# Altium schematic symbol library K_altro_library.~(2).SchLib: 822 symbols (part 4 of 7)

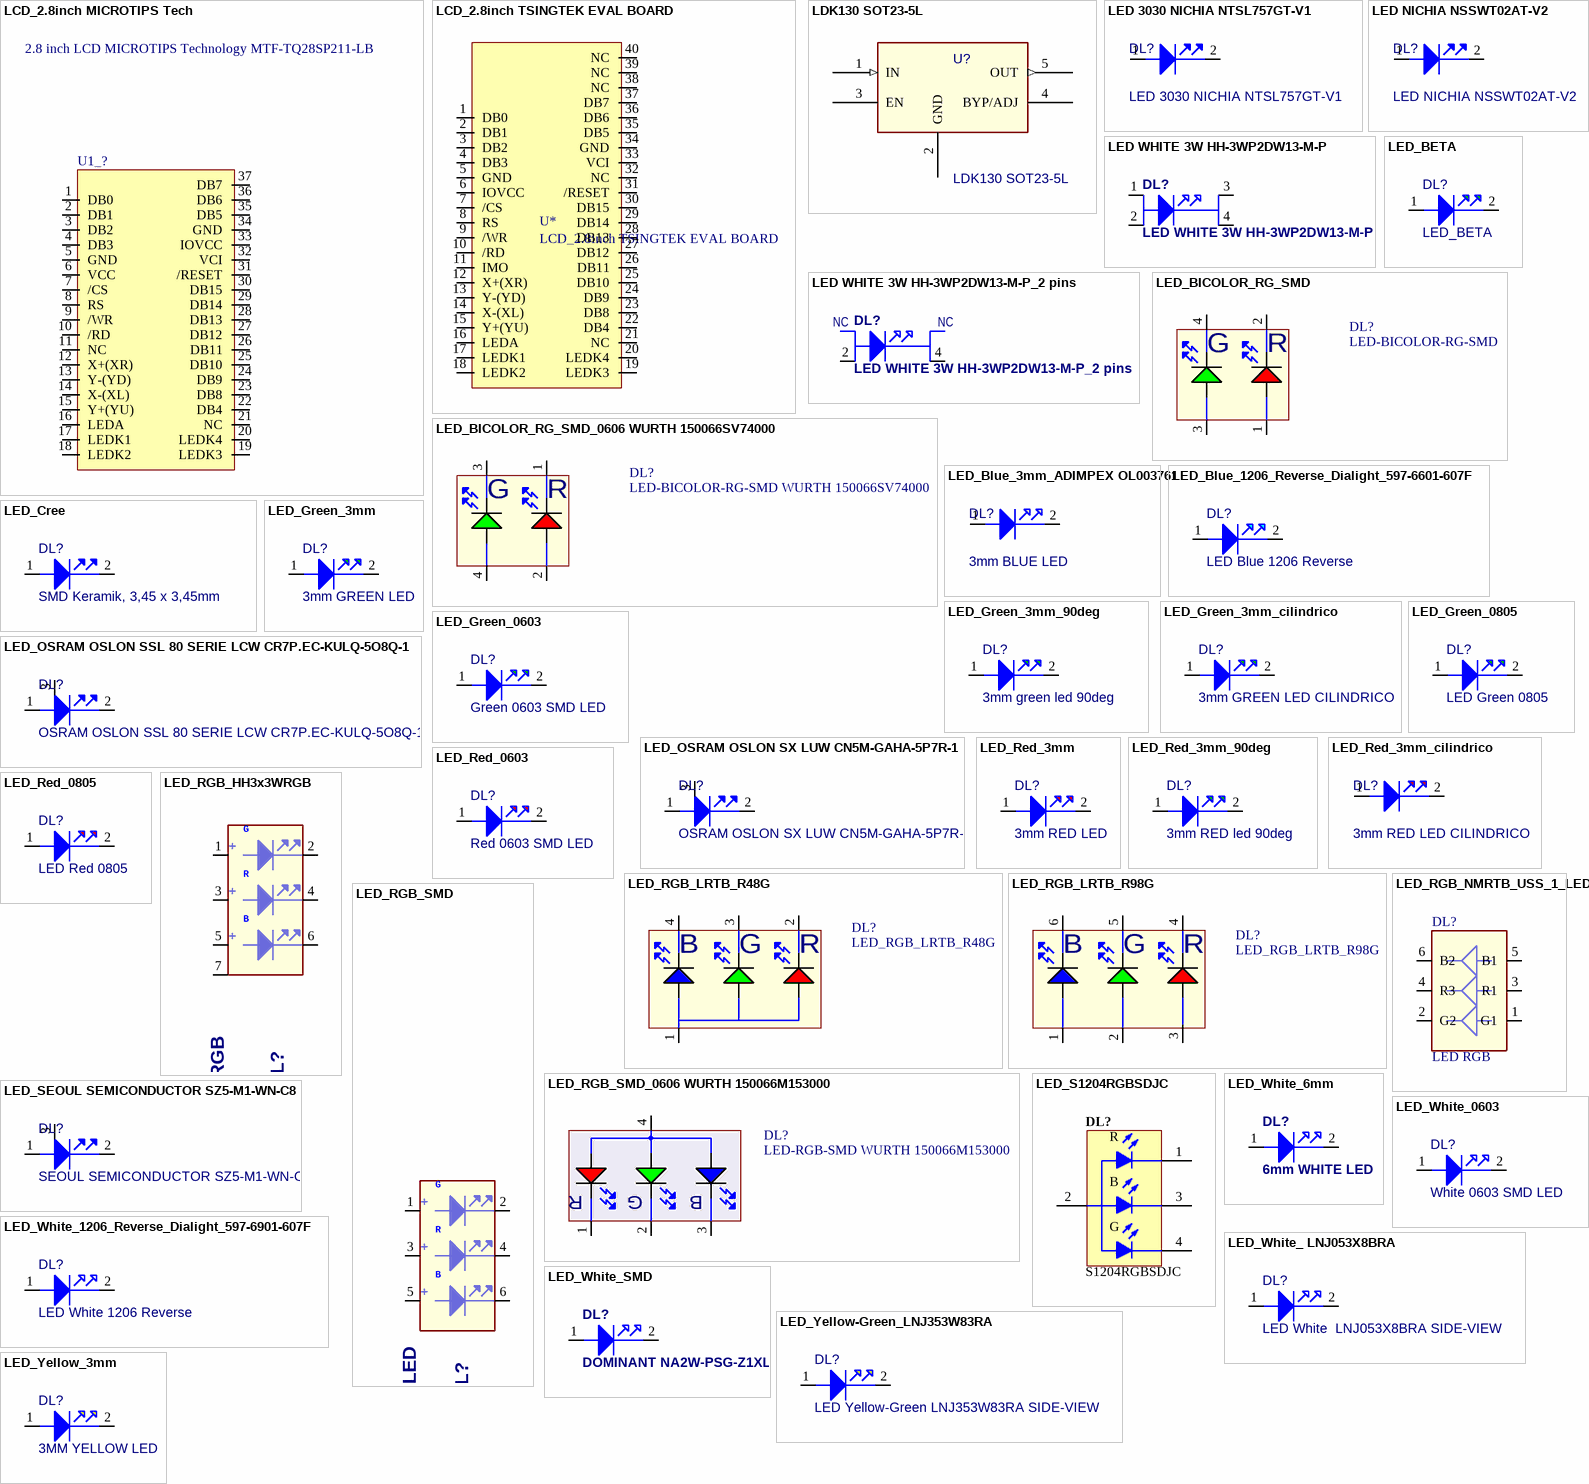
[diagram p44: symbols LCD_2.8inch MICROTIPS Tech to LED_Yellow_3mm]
## LED_Red_3mm_90deg
designator DL?, comment 3mm RED led 90deg
LED Red 3mm 90deg; Costo: 0,3; Aggiornato: s; ContoLavoro: 0
footprint 3MM RED LED 90deg H5 (Footprint not found)
pins: 1 ANODE, 2 CATHODE

## LED_Red_3mm_cilindrico
designator DL?, comment 3mm RED LED CILINDRICO
LED Red 3mm CILINDRICO; Costo: 0,10; SizeCode: Dia. 3mm; Aggiornato: s; ContoLavoro: 0
footprint 3MM CILINDRIC RED LED-DIST14mm
footprint 3MM CILINDRIC RED LED-DIST20mm
footprint 3MM CILINDRIC RED LED
pins: 1 ANODE, 2 CATHODE

## LED_Red_0603
designator DL?, comment Red 0603 SMD LED
LED Red 0603; Costo: 0; SizeCode: 0603; Aggiornato: NO
footprint 0603N_LED
pins: 1 ANODE, 2 CATHODE

## LED_Red_0805
designator DL?, comment LED Red 0805
Costo: 0,09; SizeCode: 0805; Aggiornato: S; ContoLavoro: 0
footprint LED_0805
pins: 1 ANODE, 2 CATHODE

## LED_RGB_HH3x3WRGB
designator DL?, comment RGB SMD LED HH3x3WRGB
LED RGB; Hpcode: LED0RGB001; Costo: 0,9; Aggiornato: NO; ContoLavoro: 0
footprint RGB_NMRTB_USS_1_LED
footprint RGB_NMRTB_USS_1_LED_new
footprint LED_HH3x3WRGB
pins: 1 ANODE1, 2 CATHODE1, 3 ANODE2, 4 CATHODE2, 5 ANODE3, 6 CATHODE3, 7 DIS

## LED_RGB_LRTB_R48G
designator DL?
LED RGB LRTB_R48G; Detail: € RS Pz>25; Costo: 0,148; Aggiornato: NO; ContoLavoro: 0
footprint LED_LRTB_R48G (Footprint not found)
pins: 1 AN, 2 R_CAT, 3 G_CAT, 4 B_CAT

## LED_RGB_LRTB_R98G
designator DL?
LED RGB LRTB_R98G; Detail: € RS Pz>50; Costo: 0,259; Aggiornato: NO; ContoLavoro: 0
footprint LED_LRTB_R98G
pins: 1 B_AN, 2 G_AN, 3 R_AN, 4 R_CAT, 5 G_CAT, 6 B_CAT

## LED_RGB_NMRTB_USS_1_LED
designator DL?, comment LED RGB
Costo: 0; Aggiornato: NO
footprint RGB_NMRTB_USS_1_LED
pins: 1 G1, 2 G2, 3 R1, 4 R3, 5 B1, 6 B2

## LED_RGB_SMD
designator DL?, comment DOMINANT NMRTB-WSG-AAB+ABD+X2Y-1 RGB LED
LED RGB SMD; Costo: 0; Aggiornato: NO
footprint RGB_NMRTB_USS_1_LED
footprint RGB_NMRTB_USS_1_LED_new
pins: 1 ANODE1, 2 CATHODE1, 3 ANODE2, 4 CATHODE2, 5 ANODE3, 6 CATHODE3

## LED_RGB_SMD_0606 WURTH 150066M153000
designator DL?, comment LED-RGB-SMD WURTH 150066M153000
Detail: 0,075€ 4000pcs offerta A20IT011754; Costo: 0,075; Aggiornato: S; ContoLavoro: 0
footprint LED_RGB_0606_WE_150066M153000 (LED RGB 1.6x1.6)
pins: 1 AN, 2 R_CAT, 3 G_CAT, 4 B_CAT

## LED_S1204RGBSDJC
designator DL?, comment S1204RGBSDJC
SASEN LED, RGB, SMD; Aggiornato: NO; Costo: 0
footprint S1204RGBSDJC
pins: 1 R, 2 A2, 3 B, 4 G

## LED_SEOUL SEMICONDUCTOR SZ5-M1-WN-C8
designator DL?, comment SEOUL SEMICONDUCTOR SZ5-M1-WN-C8
Detail: MATELICI ELNA; Aggiornato: si; ContoLavoro: 1
footprint LED_SEOUL SEMICONDUCTOR SZ5-M1-WN-C8 (Footprint not found)
pins: 1 ANODE, 2 CATHODE, 3 HEATER

## LED_White_6mm
designator DL?, comment 6mm WHITE LED
LED White 6mm; Hpcode: DIL6MMWHT; SizeCode: Dia. 6mm; Costo: 0; Aggiornato: NO
footprint 6MM LED (Footprint not found)
footprint 6mm_LED
pins: 1 ANODE, 2 CATHODE

## LED_White_0603
designator DL?, comment White 0603 SMD LED
LED White 0603; Detail: prezzo RS >50pz; Costo: 0,134; SizeCode: 0603; Aggiornato: n; ContoLavoro: 0
footprint 0603N_LED
pins: 1 ANODE, 2 CATHODE

## LED_White_1206_Reverse_Dialight_597-6901-607F
designator DL?, comment LED White 1206 Reverse
LED 597-6901-607F; Detail: € RS Pz>250; Costo: 0,25; SizeCode: 1206; Aggiornato: n; ContoLavoro: 0
footprint 1206_REVERSE_LED_Dialight_White (Footprint not found)
pins: 1 ANODE, 2 CATHODE

## LED_White_ LNJ053X8BRA
designator DL?, comment LED White  LNJ053X8BRA SIDE-VIEW
Detail: € Rs Pz>50; Costo: 0,274; SizeCode: KLTFSN2K5300; Aggiornato: s; ContoLavoro: 0
footprint LED_KLTFSN2K5300
simulation model DLED_GEN
pins: 1 ANODE, 2 CATHODE

## LED_White_SMD
designator DL?, comment DOMINANT NA2W-PSG-Z1XL
LED White SMD; Hpcode: LED0WHT001; Costo: 0; Aggiornato: NO
footprint 6MM LED (Footprint not found)
footprint DOMINANT_NA2WPSG
pins: 1 ANODE, 2 CATHODE

## LED_Yellow-Green_LNJ353W83RA
designator DL?, comment LED Yellow-Green LNJ353W83RA SIDE-VIEW
Detail: € Rs Pz>50; Costo: 0,235; SizeCode: KLTFSN2K5300; Aggiornato: s; ContoLavoro: 0
footprint LED_KLTFSN2K5300
simulation model DLED_GEN
pins: 1 ANODE, 2 CATHODE

## LED_Yellow_3mm
designator DL?, comment 3MM YELLOW LED
LED Yellow 3mm; Hpcode: DIL3MMYEL; SizeCode: Dia. 3mm; Costo: 0,10; Aggiornato: s; ContoLavoro: 0
footprint 3MM LED
simulation model DLED_GEN
footprint 3mm LED-DIST16mm (Footprint not found)
footprint 3mm LED-DIST22mm (Footprint not found)
pins: 1 ANODE, 2 CATHODE


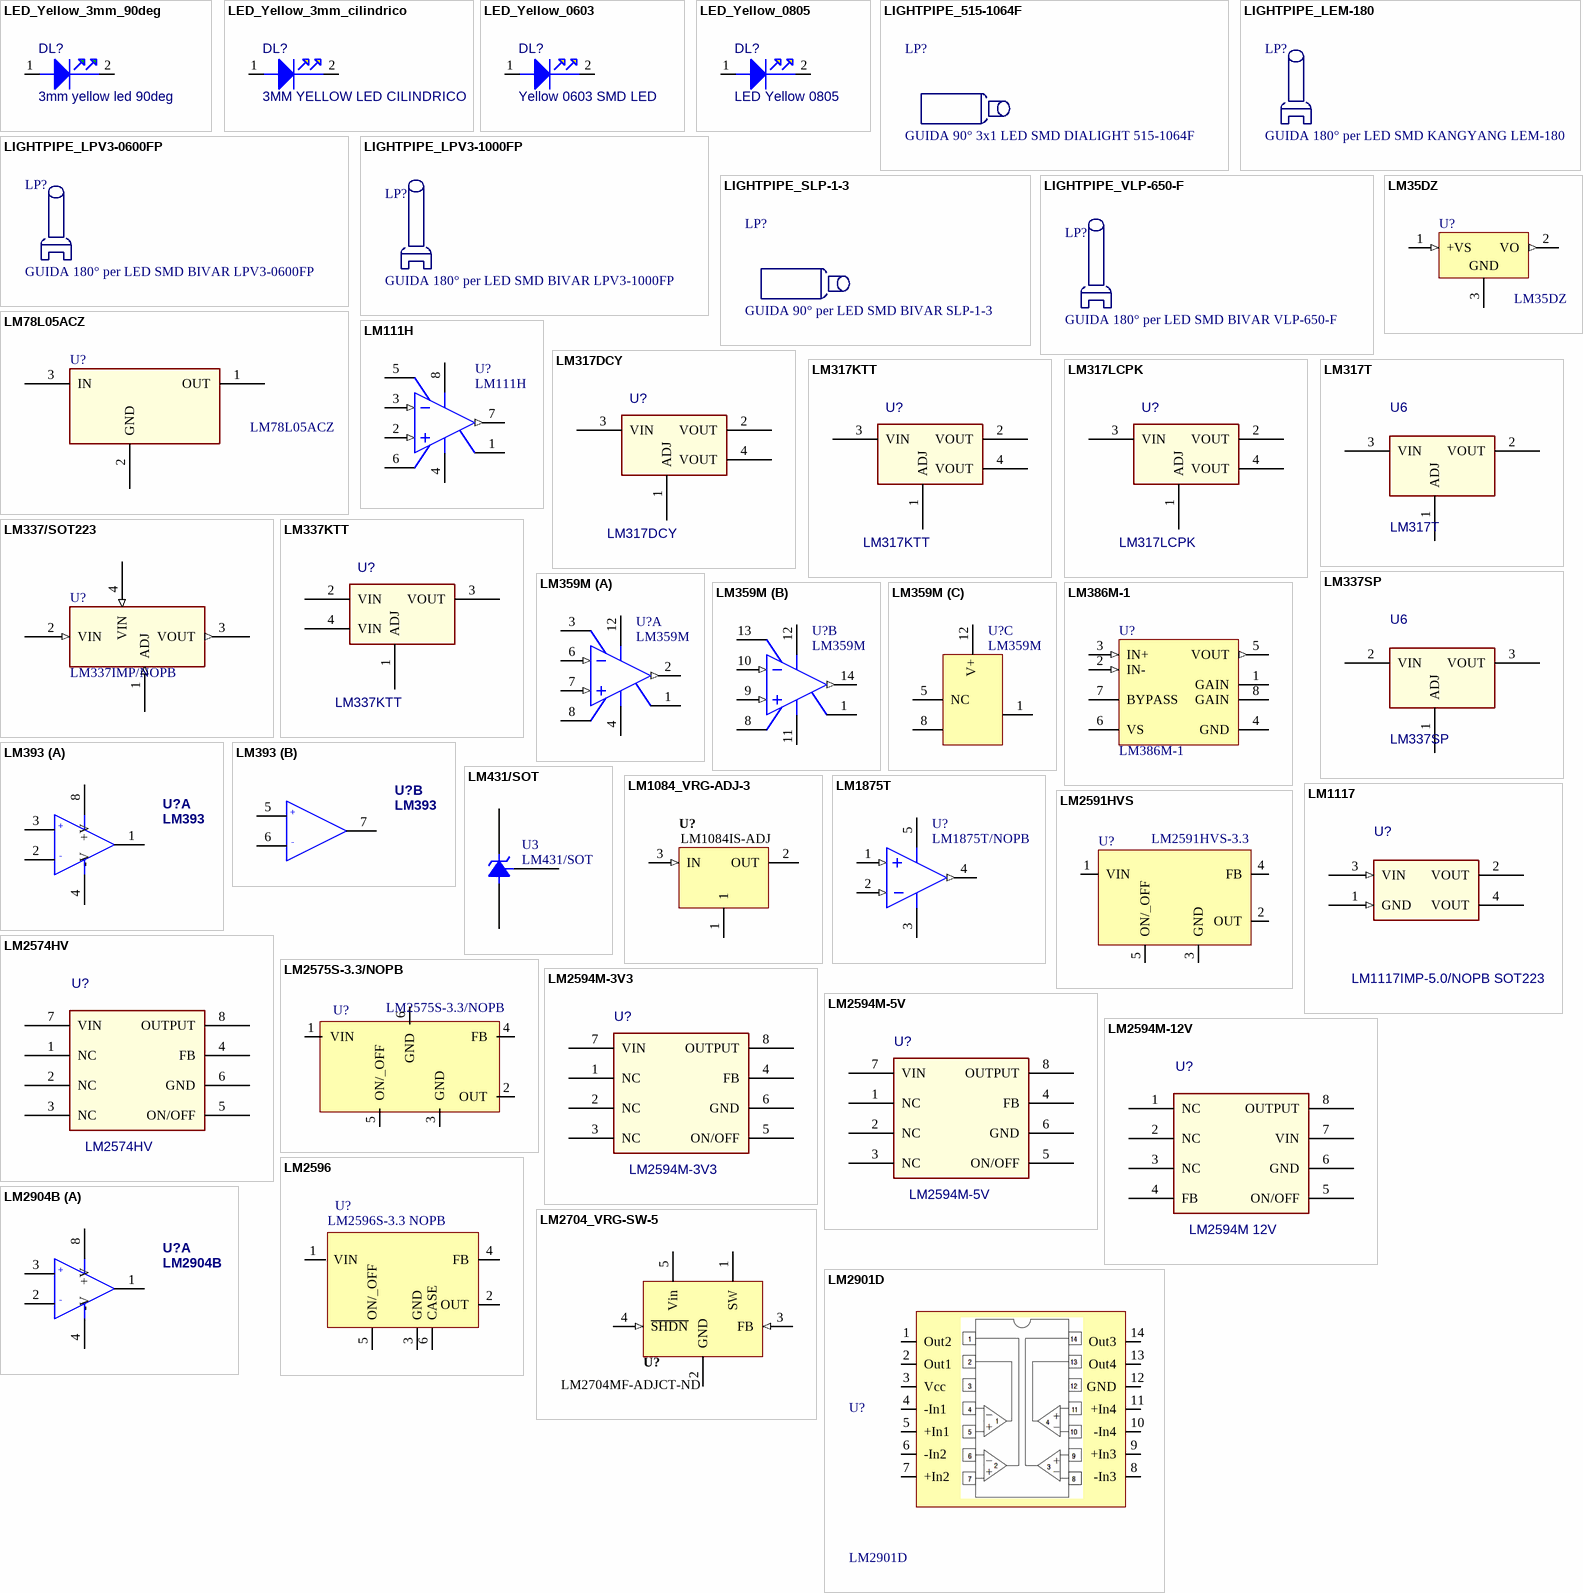
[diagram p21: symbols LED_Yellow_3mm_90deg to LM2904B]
## LED_Yellow_3mm_90deg
designator DL?, comment 3mm yellow led 90deg
LED Yellow 3mm 90deg; Costo: 1,8; Aggiornato: s; ContoLavoro: 0
footprint 3MM YEL LED 90deg H5 (Footprint not found)
simulation model DLED_GEN
pins: 1 ANODE, 2 CATHODE

## LED_Yellow_3mm_cilindrico
designator DL?, comment 3MM YELLOW LED CILINDRICO
LED Yellow 3mm CILINDRICO; SizeCode: Dia. 3mm; Costo: 0,10; Aggiornato: s; ContoLavoro: 0
footprint 3MM CILINDRIC YEL LED-DIST14mm
footprint 3MM CILINDRIC YEL LED-DIST20mm
footprint 3MM CILINDRIC YEL LED
simulation model DLED_GEN
pins: 1 ANODE, 2 CATHODE

## LED_Yellow_0603
designator DL?, comment Yellow 0603 SMD LED
LED Yellow 0603; Costo: 0; SizeCode: 0603; Aggiornato: NO
footprint 0603N_LED
pins: 1 ANODE, 2 CATHODE

## LED_Yellow_0805
designator DL?, comment LED Yellow 0805
Costo: 0,09; SizeCode: 0805; Aggiornato: s; ContoLavoro: 0
footprint LED_0805
simulation model DLED_GEN
pins: 1 ANODE, 2 CATHODE

## LIGHTPIPE_515-1064F
designator LP?, comment GUIDA 90° 3x1 LED SMD DIALIGHT 515-1064F  (no BOM)
Costo: 1; Hpcode: MMBLC153; Aggiornato: S; Detail: Parte meccanica non parte della scheda
footprint Lightpipe 3x1 (Dialight 515-1064F)
1 alternate drawing of the same symbol

## LIGHTPIPE_LEM-180
designator LP?, comment GUIDA 180° per LED SMD KANGYANG LEM-180
Costo: 0,075; Hpcode: MMBLC100; Aggiornato: S; Detail: Quotazione Orlandi HTcompo LEM-180 € 75,00/1000pcs Lead time: 2WK; ContoLavoro: 1
footprint GUIDA KANGYANG 180° LEM-180 per LED SMD (Footprint not found)
footprint GUIDA KANGYANG 180° LEM per LED SMD-IBRID_LPV_e_VLP_MONTATO_LEM-180 (Footprint not found)
1 alternate drawing of the same symbol

## LIGHTPIPE_LPV3-0600FP
designator LP?, comment GUIDA 180° per LED SMD BIVAR LPV3-0600FP
Costo: 0; Aggiornato: S; ContoLavoro: 1
footprint GUIDA BIVAR 180° LPV3-0600FP per LED SMD (Footprint not found)
footprint GUIDA BIVAR 180° VLP per LED SMD-IBRID_LPV_MONTATO_LPV3-0600FP
1 alternate drawing of the same symbol

## LIGHTPIPE_LPV3-1000FP
designator LP?, comment GUIDA 180° per LED SMD BIVAR LPV3-1000FP
Costo: 0; Aggiornato: S; ContoLavoro: 1
footprint GUIDA BIVAR 180° LPV3-1000FP per LED SMD
footprint GUIDA BIVAR 180° VLP per LED SMD-IBRID_LPV_MONTATO_LPV3-1000FP
1 alternate drawing of the same symbol

## LIGHTPIPE_SLP-1-3
designator LP?, comment GUIDA 90° per LED SMD BIVAR SLP-1-3  (no BOM)
Costo: 0,5; Hpcode: MMBLC094; Aggiornato: S; Detail: Parte meccanica non parte della scheda; ContoLavoro: 1
footprint GUIDA_BIVAR_90°_SLP-1-3 (Guida 90° per led SMD)
1 alternate drawing of the same symbol

## LIGHTPIPE_VLP-650-F
designator LP?, comment GUIDA 180° per LED SMD BIVAR VLP-650-F
Costo: 0,308; Aggiornato: S; Detail: 0,308€ Mouser Pz> 25; ContoLavoro: 1
footprint GUIDA BIVAR 180° VLP-650-F per LED SMD (Footprint not found)
footprint GUIDA BIVAR 180° VLP per LED SMD-IBRID_LPV_MONTATO_VLP-650-F
1 alternate drawing of the same symbol

## LM35DZ
designator U?
Precision Centigrade Temperature Sensor; Costo: 0; DeviceFunction: Temperature Sensors; Aggiornato: NO
footprint Z03A (TO, Flat Index; 3 In-Line, Axial Leads; Body Dia. 5mm; Leads 0.55 x 0.50 mm (max))
pins: 1 +VS (in), 2 VO (out), 3 GND (power)

## LM78L05ACZ
designator U?
Costo: 0; DeviceFunction: Voltage Regulator; Aggiornato: NO
footprint TO92/100/123
pins: 1 OUT, 2 GND, 3 IN

## LM111H
designator U?
Voltage Comparator; DeviceFunction: Amplifier; Costo: 0; Aggiornato: NO
footprint H08C (Can; 8 Leads; Pin Circle Dia. 5.08 mm; Lead Dia. 0.48 mm (max))
simulation model LM111 (SUBCKT)
pins: 1 GND (power), 2 IN+ (in), 3 IN- (in), 4 V- (power), 5 BAL, 6 BAL/STB, 7 OUT (out), 8 V+ (power)

## LM317DCY
designator U?
Costo: 0,50; DeviceFunction: Voltage Regulator; Aggiornato: NO; ContoLavoro: 0
footprint SOT223_LM317DCY
pins: 1 ADJ, 2 VOUT, 3 VIN, 4 VOUT

## LM317KTT
designator U?
LM317KTT LM317 TO-263 DDPAK D2PAK; Costo: 0,50; DeviceFunction: Voltage Regulator; Aggiornato: s; ContoLavoro: 0
footprint TO263_3PIN (TO263 3 PIN DDPAK D2PAK LM317KTT LM337KTT)
footprint TO220_123_TO263_Ibrid (TO-220 TO-263 Ibrid)
footprint TO220_123_TO263_Ibrid2 (TO-220 TO-263 Ibrid)
pins: 1 ADJ, 2 VOUT, 3 VIN, 4 VOUT

## LM317LCPK
designator U?
Costo: 0,30; DeviceFunction: Voltage Regulator; Aggiornato: NO; ContoLavoro: 0
footprint SOT89_DPLS350Y
pins: 1 ADJ, 2 VOUT, 3 VIN, 4 VOUT

## LM317T
designator U6
LM317T TO220; Costo: 0,4; Aggiornato: S; ContoLavoro: 0
footprint TO220_123
pins: 1 ADJ, 2 VOUT, 3 VIN

## LM337/SOT223
designator U?, comment LM337IMP/NOPB
Costo: 1,36; DeviceFunction: Voltage Regulator; Aggiornato: NO; ContoLavoro: 0
footprint SOT223
pins: 1 ADJ (in), 2 VIN (in), 3 VOUT (out), 4 VIN (in)

## LM337KTT
designator U?
LM337KTT LM337 TO-263 DDPAK D2PAK; Costo: 1; DeviceFunction: Voltage Regulator; Aggiornato: s; ContoLavoro: 0
footprint TO263_3PIN (TO263 3 PIN DDPAK D2PAK LM317KTT LM337KTT)
footprint TO220_123_TO263_Ibrid (TO-220 TO-263 Ibrid)
footprint TO220_123_TO263_Ibrid2 (TO-220 TO-263 Ibrid)
pins: 1 ADJ, 2 VIN, 3 VOUT, 4 VIN

## LM337SP
designator U6
LM337SP TO220; Costo: 0,5; Aggiornato: S; ContoLavoro: 0
footprint TO220_123
pins: 1 ADJ, 2 VIN, 3 VOUT

## LM359M
designator U?
Dual, High Speed, Programmable, Current Mode (Norton) Amplifiers; Costo: 0; Aggiornato: NO
footprint M14A_N (SOIC, 14-Leads, Body 8.6x3.9mm, Pitch 1.27mm, IPC Medium Density)
footprint M14A_L (SOIC, 14-Leads, Body 8.6x3.9mm, Pitch 1.27mm, IPC High Density)
footprint M14A_M (SOIC, 14-Leads, Body 8.6x3.9mm, Pitch 1.27mm, IPC Low Density)
simulation model LM359 (SUBCKT)
pins on every part: 1 ISET(OUT), 8 ISET(IN), 12 V+ (power)
part A pins: 2 OUTA (out), 3 COMPA, 4 GNDA (power), 6 INA- (in), 7 INA+ (in)
part B pins: 9 INB+ (in), 10 INB- (in), 11 GNDB (power), 13 COMPB, 14 OUTB (out)
part C pins: 5 NC

## LM386M-1
designator U?
Low Voltage Audio Power Amplifier; Costo: 0; Aggiornato: NO
footprint SO8
pins: 1 GAIN, 2 IN- (in), 3 IN+ (in), 4 GND (power), 5 VOUT (out), 6 VS (power), 7 BYPASS, 8 GAIN

## LM393
designator U?
LM393 dual comparator open collector out; Costo: 0,118; Aggiornato: SI; ContoLavoro: 0
footprint SO8
footprint SOIC150-8N
part A pins: 1 OUT, 2 -IN, 3 +IN, 4 -V, 8 +V
part B pins: 5 +IN, 6 -IN, 7 OUT

## LM431/SOT
designator U3
Costo: 0; Aggiornato: NO
footprint SOT-23_UP
pins: 1 K, 2 REF, 3 A

## LM1084_VRG-ADJ-3
designator U?, comment LM1084IS-ADJ
LM1084IS-ADJ, 5A Low Dropout Positive Regulators; Max Input Voltage: mV; Max Output Current: mA; Aggiornato: NO; Costo: 0
footprint TO254P1435-4
footprint TO-263-H
pins: 1 "Output", 2 OUT (power) "Output", 3 IN (in) "Input", 4 HeatSink (power)

## LM1117
designator U?, comment LM1117IMP-5.0/NOPB SOT223
Costo: 0; DeviceFunction: Voltage Regulator; Aggiornato: NO
footprint SOT223
pins: 1 GND (in), 2 VOUT, 3 VIN (in), 4 VOUT

## LM1875T
designator U?, comment LM1875T/NOPB
Amplificatore audio LM1875T/NOPB Classe AB mono; Costo: 2,24; Aggiornato: SI; ContoLavoro: 0
footprint TO220_5P
pins: 1 IN+ (in), 2 IN- (in), 3 V- (power), 4 OUT (out), 5 V+ (power)

## LM2574HV
designator U?
Costo: 0; DeviceFunction: Voltage Regulator; Aggiornato: NO
footprint SO8
pins: 1 NC, 2 NC, 3 NC, 4 FB, 5 ON/OFF, 6 GND, 7 VIN, 8 OUTPUT

## LM2575S-3.3/NOPB
designator U?
Costo: 2,024; DeviceFunction: SWITCHER; Aggiornato: SI; ContoLavoro: 0
footprint TO263_5PIN
pins: 1 VIN, 2 OUT, 3 GND, 4 FB, 5 ON/_OFF, 6 GND

## LM2591HVS
designator U?, comment LM2591HVS-3.3
Costo: 0; DeviceFunction: SWITCHER; Aggiornato: NO
footprint TO263_5PIN
pins: 1 VIN, 2 OUT, 3 GND, 4 FB, 5 ON/_OFF

## LM2594M-3V3
designator U?
Costo: 2,50; Aggiornato: s; ContoLavoro: 0
footprint SO8
pins: 1 NC, 2 NC, 3 NC, 4 FB, 5 ON/OFF, 6 GND, 7 VIN, 8 OUTPUT

## LM2594M-5V
designator U?
Costo: 2,50; Aggiornato: s; ContoLavoro: 0
footprint SO8
pins: 1 NC, 2 NC, 3 NC, 4 FB, 5 ON/OFF, 6 GND, 7 VIN, 8 OUTPUT

## LM2594M-12V
designator U?, comment LM2594M 12V
LM2594M-12V; Costo: 3,00; DeviceFunction: Switching Regulator 12v; Aggiornato: s; ContoLavoro: 0
footprint SO8
pins: 1 NC, 2 NC, 3 NC, 4 FB, 5 ON/OFF, 6 GND, 7 VIN, 8 OUTPUT

## LM2596
designator U?, comment LM2596S-3.3 NOPB
LM2596; Costo: 0; DeviceFunction: SWITCHER; Aggiornato: NO
footprint TO263_5PIN
pins: 1 VIN, 2 OUT, 3 GND, 4 FB, 5 ON/_OFF, 6 CASE

## LM2704_VRG-SW-5
designator U?, comment LM2704MF-ADJCT-ND
LM2704MF, Micropower Step-up DC/DC Converter, 550mA Peak Current Limit, 2.2-7V Input, 20V Max Output; Aggiornato: NO; Costo: 0
footprint SOT95P284-5
pins: 1 SW (oc), 2 GND (power), 3 FB (in), 4 ~{SHDN} (in), 5 Vin (power)

## LM2901D
designator U?
LM2901 Single Supply Quad  Comparators; Aggiornato: n; Costo: 0,109; ContoLavoro: 0; Details: € Rs Pz>100
footprint SOIC14 (Footprint not found)
pins: 1 Out2, 2 Out1, 3 Vcc, 4 -In1, 5 +In1, 6 -In2, 7 +In2, 8 -In3, 9 +In3, 10 -In4, 11 +In4, 12 GND, 13 Out4, 14 Out3


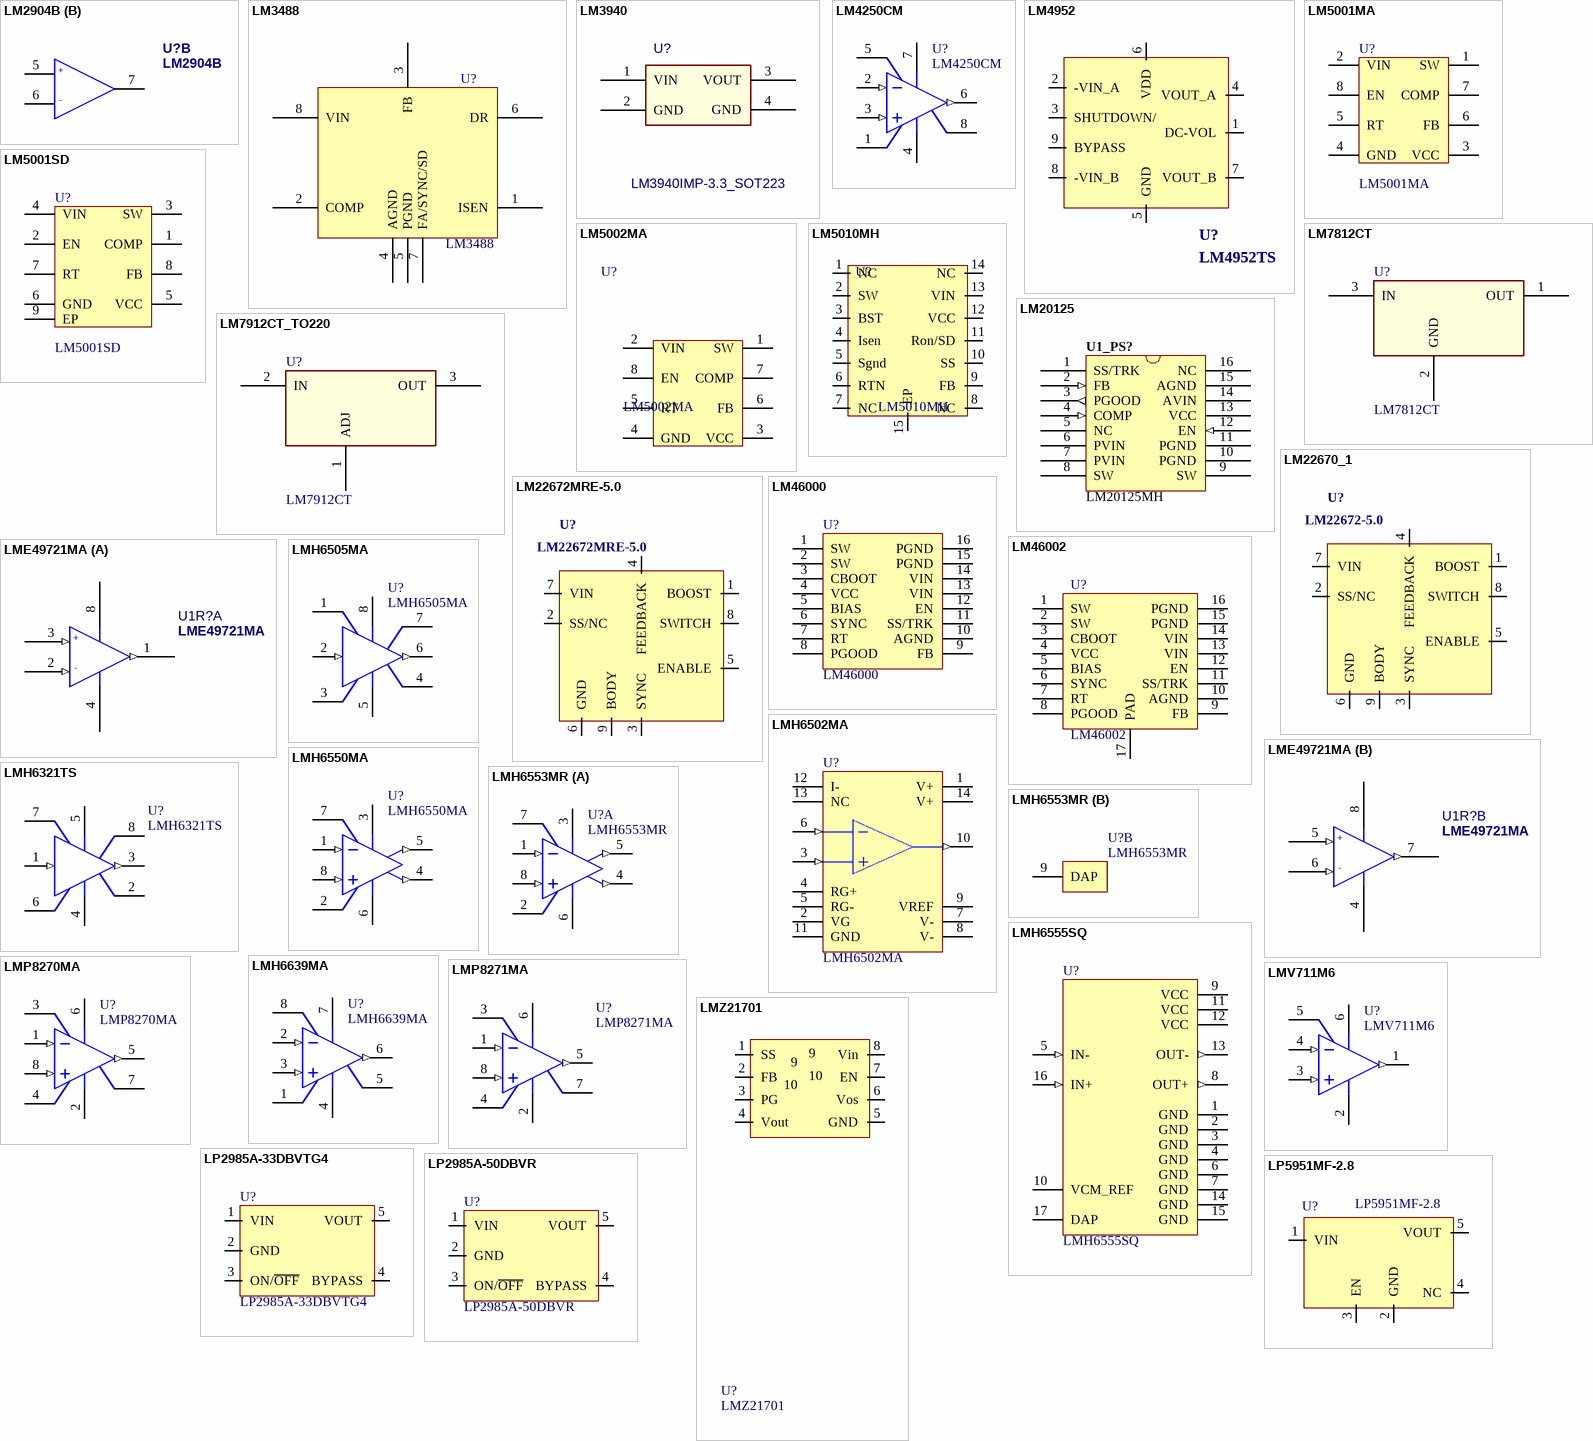
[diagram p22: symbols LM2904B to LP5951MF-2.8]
## LM2904B
designator U?
Detail: €0,081 > 1000pz Mouser; Costo: 0,08; Aggiornato: S; ContoLavoro: 0
footprint SO8
footprint SOIC150-8N
part A pins: 1 OUT, 2 -IN, 3 +IN, 4 -V, 8 +V
part B pins: 5 +IN, 6 -IN, 7 OUT

## LM3488
designator U?
Costo: 0; DeviceFunction: SWITCHER; Aggiornato: NO
footprint MUA08A_N (TSOP, 8-Leads, Body 3x3mm, Pitch 0.65mm, IPC Medium Density)
pins: 1 ISEN, 2 COMP, 3 FB, 4 AGND, 5 PGND, 6 DR, 7 FA/SYNC/SD, 8 VIN

## LM3940
designator U?, comment LM3940IMP-3.3_SOT223
Costo: 1,13; DeviceFunction: Voltage Regulator; Aggiornato: NO; ContoLavoro: 0
footprint SOT223
pins: 1 VIN, 2 GND, 3 VOUT, 4 GND

## LM4250CM
designator U?
Programmable Operational Amplifier; Costo: 0; Aggiornato: NO
footprint M08A_N (SOIC, 8-Leads, Body 4.9x3.9mm, Pitch 1.27mm, IPC Medium Density)
footprint M08A_L (SOIC, 8-Leads, Body 4.9x3.9mm, Pitch 1.27mm, IPC High Density)
footprint M08A_M (SOIC, 8-Leads, Body 4.9x3.9mm, Pitch 1.27mm, IPC Low Density)
simulation model LM4250 (SUBCKT)
pins: 1 OFS NULL, 2 IN- (in), 3 IN+ (in), 4 V- (power), 5 OFS NULL, 6 OUT (out), 7 V+ (power), 8 I SET

## LM4952
designator U?, comment LM4952TS
Costo: 0; DeviceFunction: Amplifier; Aggiornato: NO
footprint TO263_9PIN
pins: 1 DC-VOL, 2 -VIN_A, 3 SHUTDOWN/, 4 VOUT_A, 5 GND, 6 VDD, 7 VOUT_B, 8 -VIN_B, 9 BYPASS

## LM5001MA
designator U?
High Voltage Switch Mode Regulator; Aggiornato: si; Costo: 2; ContoLavoro: 0
footprint SO8
pins: 1 SW, 2 VIN, 3 VCC, 4 GND, 5 RT, 6 FB, 7 COMP, 8 EN

## LM5001SD
designator U?
High Voltage Switch Mode Regulator; Manufacturer: National Semiconductor; CompType: MiscPower; PackageTopMarking: NS*UZXYTT*LM5001; Aggiornato: NO; Costo: 0
footprint SDC08A (SON, 8-Leads, Body 4x4mm, Pitch 0.8mm, NSC Recommended)
pins: 1 COMP, 2 EN, 3 SW, 4 VIN, 5 VCC, 6 GND, 7 RT, 8 FB, 9 EP

## LM5002MA
designator U?
High Voltage Switch Mode Regulator; Costo: 2,252; Aggiornato: s; ContoLavoro: 0
footprint SO8
pins: 1 SW, 2 VIN, 3 VCC, 4 GND, 5 RT, 6 FB, 7 COMP, 8 EN

## LM5010MH
designator U?
High Voltage Switch Mode Regulator; Detail: Costo RS >100pz; Costo: 2,86; Aggiornato: s; ContoLavoro: 0
footprint TSSOP14EP
pins: 1 NC, 2 SW, 3 BST, 4 Isen, 5 Sgnd, 6 RTN, 7 NC, 8 NC, 9 FB, 10 SS, 11 Ron/SD, 12 VCC, 13 VIN, 14 NC, 15 EP

## LM7812CT
designator U?
Costo: 0; DeviceFunction: Voltage Regulator; Aggiornato: NO
footprint TO220_123
pins: 1 OUT, 2 GND, 3 IN

## LM7912CT_TO220
designator U?, comment LM7912CT
Costo: 0; DeviceFunction: Voltage Regulator; Aggiornato: NO
footprint TO220_123
footprint TO220 123
pins: 1 ADJ, 2 IN, 3 OUT

## LM20125
designator U1_PS?, comment LM20125MH
LM20125MH, 5A, Synchronous Buck Regulator; Costo: 0; Aggiornato: NO
footprint TSOP65P638-16
pins: 1 SS/TRK, 2 FB (in), 3 PGOOD (out), 4 COMP (in), 5 NC, 6 PVIN, 7 PVIN, 8 SW, 9 SW, 10 PGND (power), 11 PGND (power), 12 EN (in), 13 VCC, 14 AVIN, 15 AGND, 16 NC

## LM22670_1
designator U?, comment LM22672-5.0
Costo: 0; DeviceFunction: SWITCHER; Aggiornato: NO
footprint PSOP-8
footprint SOIC600_HS-8AM (SOIC, 8-Leads, Body 4.9x3.9mm, Pitch 1.27mm, Exposed Pad, IPC Low Density)
pins: 1 BOOST, 2 SS/NC, 3 SYNC, 4 FEEDBACK, 5 ENABLE, 6 GND, 7 VIN, 8 SWITCH, 9 BODY

## LM22672MRE-5.0
designator U?
Costo: 3; DeviceFunction: SWITCHER; Aggiornato: SI; ContoLavoro: 0
footprint PSOP-8
footprint SOIC600_HS-8AM (SOIC, 8-Leads, Body 4.9x3.9mm, Pitch 1.27mm, Exposed Pad, IPC Low Density)
pins: 1 BOOST, 2 SS/NC, 3 SYNC, 4 FEEDBACK, 5 ENABLE, 6 GND, 7 VIN, 8 SWITCH, 9 BODY

## LM46000
designator U?
LM46000 SIMPLE SWITCHER; Aggiornato: s; Costo: 2,5; ContoLavoro: 0
footprint HTSSOP16
pins: 1 SW, 2 SW, 3 CBOOT, 4 VCC, 5 BIAS, 6 SYNC, 7 RT, 8 PGOOD, 9 FB, 10 AGND, 11 SS/TRK, 12 EN, 13 VIN, 14 VIN, 15 PGND, 16 PGND

## LM46002
designator U?
LM46002 SIMPLE SWITCHER; Aggiornato: s; Costo: 2,5; ContoLavoro: 0
footprint HTSSOP16 _THERMALPADS
pins: 1 SW, 2 SW, 3 CBOOT, 4 VCC, 5 BIAS, 6 SYNC, 7 RT, 8 PGOOD, 9 FB, 10 AGND, 11 SS/TRK, 12 EN, 13 VIN, 14 VIN, 15 PGND, 16 PGND, 17 PAD

## LME49721MA
designator U1R?
Hpcode: ICLME49721MA; Aggiornato: NO; Costo: 0
footprint SO8
part A pins: 1 OUT (out), 2 -IN (in), 3 +IN (in), 4 -V2 (power), 8 +V2 (power)
part B pins: 4 -V2 (power), 5 +IN (in), 6 -IN (in), 7 OUT (out), 8 +V2 (power)

## LMH6321TS
designator U?
300 mA High Speed Buffer with Adjustable Current Limit; DeviceFunction: Buffer Amplifier; Costo: 0; Aggiornato: NO
footprint TS7B_N (D2-PAK, 8-Leads, Body 8.6x10.2mm, Pitch 1.27mm, Lead Span 14.1mm, IPC Medium Density)
footprint TS7B_L (D2-PAK, 8-Leads, Body 8.6x10.2mm, Pitch 1.27mm, Lead Span 14.1mm, IPC High Density)
footprint TS7B_M (D2-PAK, 8-Leads, Body 8.6x10.2mm, Pitch 1.27mm, Lead Span 14.1mm, IPC Low Density)
simulation model LMH6321 (SUBCKT)
pins: 1 IN (in), 2 GND (power), 3 OUT (out), 4 V- (power), 5 V+ (power), 6 EF, 7 CL, 8 DAP

## LMH6502MA
designator U?
Wideband, Low Power, Linear-in-dB Variable Gain Amplifier; Costo: 0; Aggiornato: NO
footprint M14A_N (SOIC, 14-Leads, Body 8.6x3.9mm, Pitch 1.27mm, IPC Medium Density)
footprint M14A_L (SOIC, 14-Leads, Body 8.6x3.9mm, Pitch 1.27mm, IPC High Density)
footprint M14A_M (SOIC, 14-Leads, Body 8.6x3.9mm, Pitch 1.27mm, IPC Low Density)
simulation model LMH6502 (SUBCKT)
pins: 1 V+ (power), 2 VG, 3 VIN+ (in), 4 RG+, 5 RG-, 6 VIN- (in), 7 V- (power), 8 V- (power), 9 VREF, 10 VOUT (out), 11 GND (power), 12 I-, 13 NC, 14 V+ (power)

## LMH6505MA
designator U?
Wideband, Low Power, Linear-in-dB, Variable Gain Amplifier; DeviceFunction: Buffer Amplifier; Costo: 0; Aggiornato: NO
footprint M08A_N (SOIC, 8-Leads, Body 4.9x3.9mm, Pitch 1.27mm, IPC Medium Density)
footprint M08A_L (SOIC, 8-Leads, Body 4.9x3.9mm, Pitch 1.27mm, IPC High Density)
footprint M08A_M (SOIC, 8-Leads, Body 4.9x3.9mm, Pitch 1.27mm, IPC Low Density)
simulation model LMH6505 (SUBCKT)
pins: 1 VG, 2 VIN (in), 3 RG, 4 GND (power), 5 V- (power), 6 VOUT (out), 7 I-, 8 V+ (power)

## LMH6550MA
designator U?
Differential, High Speed Op Amp; DeviceFunction: Differential Amplifier; Costo: 0; Aggiornato: NO
footprint M08A_N (SOIC, 8-Leads, Body 4.9x3.9mm, Pitch 1.27mm, IPC Medium Density)
footprint M08A_L (SOIC, 8-Leads, Body 4.9x3.9mm, Pitch 1.27mm, IPC High Density)
footprint M08A_M (SOIC, 8-Leads, Body 4.9x3.9mm, Pitch 1.27mm, IPC Low Density)
simulation model LMH6550 (SUBCKT)
pins: 1 IN- (in), 2 VCM, 3 V+ (power), 4 OUT+ (out), 5 OUT- (out), 6 V- (power), 7 EN, 8 IN+ (in)

## LMH6553MR
designator U?
900 MHz Fully Differential Amplifier with Output Limiting Clamp; Costo: 0; Aggiornato: NO
footprint MRA08B_N (SOIC, 8-Leads, Body 4.9x3.9mm, Pitch 1.27mm, Exposed Pad, IPC Medium Density)
footprint MRA08B_L (SOIC, 8-Leads, Body 4.9x3.9mm, Pitch 1.27mm, Exposed Pad, IPC High Density)
footprint MRA08B_M (SOIC, 8-Leads, Body 4.9x3.9mm, Pitch 1.27mm, Exposed Pad, IPC Low Density)
simulation model LMH6553 (SUBCKT)
part A pins: 1 IN- (in), 2 VCM, 3 V+ (power), 4 OUT+ (out), 5 OUT- (out), 6 V- (power), 7 VCLAMP, 8 IN+ (in)
part B pins: 9 DAP

## LMH6555SQ
designator U?
Low Distortion 1.2 GHz Differential Driver; DeviceFunction: Differential Amplifier; Costo: 0; Aggiornato: NO
footprint SQA16A (QFN, 16-Leads, Body 4x4mm, Pitch 0.5mm, NSC Recommended)
simulation model LMH6555 (SUBCKT)
pins: 1 GND (power), 2 GND (power), 3 GND (power), 4 GND (power), 5 IN- (in), 6 GND (power), 7 GND (power), 8 OUT+ (out), 9 VCC (power), 10 VCM_REF, 11 VCC (power), 12 VCC (power), 13 OUT- (out), 14 GND (power), 15 GND (power), 16 IN+ (in), 17 DAP

## LMH6639MA
designator U?
190MHz Rail-to-Rail Output Amplifier with Disable; Costo: 0; Aggiornato: NO
footprint M08A_N (SOIC, 8-Leads, Body 4.9x3.9mm, Pitch 1.27mm, IPC Medium Density)
footprint M08A_L (SOIC, 8-Leads, Body 4.9x3.9mm, Pitch 1.27mm, IPC High Density)
footprint M08A_M (SOIC, 8-Leads, Body 4.9x3.9mm, Pitch 1.27mm, IPC Low Density)
simulation model LMH6639 (SUBCKT)
pins: 1 NC, 2 IN- (in), 3 IN+ (in), 4 V- (power), 5 NC, 6 OUT (out), 7 V+ (power), 8 ~{SD}

## LMP8270MA
designator U?
High Common Mode, Gain of 20, Precision Voltage Difference Amplifier; DeviceFunction: Differential Amplifier; Costo: 0; Aggiornato: NO
footprint M08A_N (SOIC, 8-Leads, Body 4.9x3.9mm, Pitch 1.27mm, IPC Medium Density)
footprint M08A_L (SOIC, 8-Leads, Body 4.9x3.9mm, Pitch 1.27mm, IPC High Density)
footprint M08A_M (SOIC, 8-Leads, Body 4.9x3.9mm, Pitch 1.27mm, IPC Low Density)
simulation model LMP8270 (SUBCKT)
pins: 1 IN- (in), 2 GND (power), 3 A1, 4 A2, 5 OUT (out), 6 VS (power), 7 NC, 8 IN+ (in)

## LMP8271MA
designator U?
High Common Mode, Gain of 20, Bidirectional Precision Voltage Difference Amplifier; DeviceFunction: Differential Amplifier; Costo: 0; Aggiornato: NO
footprint M08A_N (SOIC, 8-Leads, Body 4.9x3.9mm, Pitch 1.27mm, IPC Medium Density)
footprint M08A_L (SOIC, 8-Leads, Body 4.9x3.9mm, Pitch 1.27mm, IPC High Density)
footprint M08A_M (SOIC, 8-Leads, Body 4.9x3.9mm, Pitch 1.27mm, IPC Low Density)
simulation model LMP8271 (SUBCKT)
pins: 1 IN- (in), 2 GND (power), 3 A1, 4 A2, 5 OUT (out), 6 VS (power), 7 OFS, 8 IN+ (in)

## LMV711M6
designator U?
Low Power, RRIO Operational Amplifiers with High Output Current Drive and Shutdown Option; Costo: 0; Aggiornato: NO
footprint MF06A_N (SOT23, 6-Leads, Body 2.9x1.6mm, Pitch 0.95mm, Lead Span 2.8mm, IPC Medium Density)
footprint MF06A_L (SOT23, 6-Leads, Body 2.9x1.6mm, Pitch 0.95mm, Lead Span 2.8mm, IPC High Density)
footprint MF06A_M (SOT23, 6-Leads, Body 2.9x1.6mm, Pitch 0.95mm, Lead Span 2.8mm, IPC Low Density)
simulation model LMV711 (SUBCKT)
pins: 1 OUT (out), 2 V- (power), 3 IN+ (in), 4 IN- (in), 5 SHDN, 6 V+ (power)

## LMZ21701
designator U?
LMZ21701 step-down; Aggiornato: S; Costo: 1; ContoLavoro: 0
footprint SIL0008E
pins: 1 SS, 2 FB, 3 PG, 4 Vout, 5 GND, 6 Vos, 7 EN, 8 Vin, 9 hidden, 10 hidden

## LP2985A-33DBVTG4
designator U?
Detail: €0,604 RS pz>130; Aggiornato: S; Costo: 0,604; ContoLavoro: 0
footprint SOT-23 5PIN
pins: 1 VIN, 2 GND, 3 ON/~{OFF}, 4 BYPASS, 5 VOUT

## LP2985A-50DBVR
designator U?
Detail: €0,311 Farnell pz>100; Aggiornato: S; Costo: 0,311; ContoLavoro: 0
footprint SOT-23 5PIN
pins: 1 VIN, 2 GND, 3 ON/~{OFF}, 4 BYPASS, 5 VOUT

## LP5951MF-2.8
designator U?
LP5951MG-2.8; Costo: 0,228; DeviceFunction: Voltage Regulator; Aggiornato: SI; ContoLavoro: 0
footprint SOT-23 5PIN
footprint SOT23-5AN (SOT23, 5-Leads, Body 2.9x1.6mm, Pitch 0.95mm, Lead Span 2.8mm, IPC Medium Density)
pins: 1 VIN, 2 GND, 3 EN, 4 NC, 5 VOUT


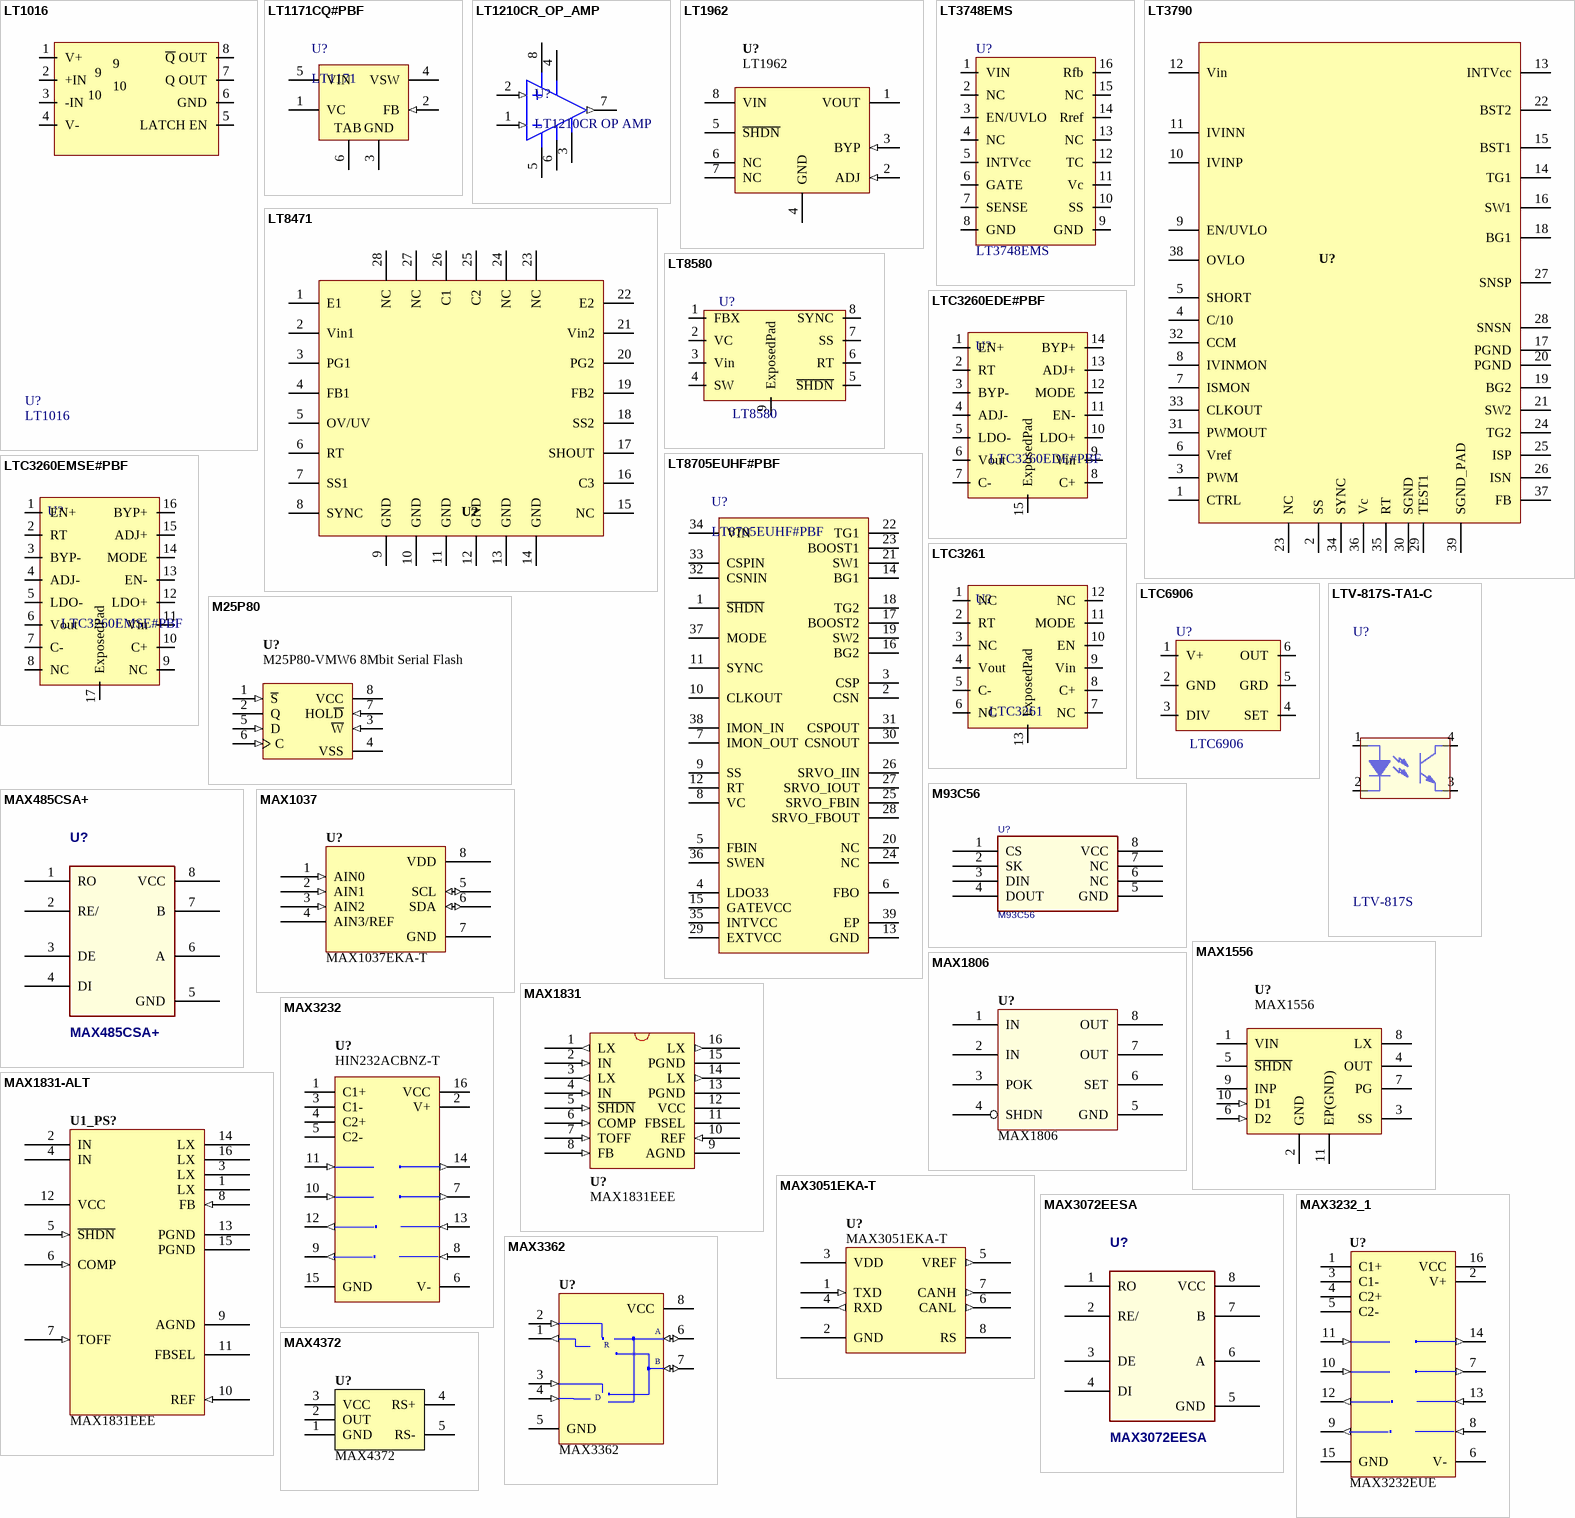
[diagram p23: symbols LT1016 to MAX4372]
## LT1016
designator U?
LT1016 is an UltraFast 10ns comparator that interfaces / directly to TTL/CMOS; Aggiornato: S; Costo: 1; ContoLavoro: 0
footprint SIL0008E
pins: 1 V+, 2 +IN, 3 -IN, 4 V-, 5 LATCH EN, 6 GND, 7 Q OUT, 8 ~{Q} OUT, 9 hidden, 10 hidden

## LT1171CQ#PBF
designator U?, comment LT1171
LT1171 100kHz, 2.5 A High Efficiency Switching Regulator; Manufacturer: Linear Technology; Frequency Sync Range: 120kHz - 160kHz; Costo: 5; ContoLavoro: 0
footprint LT-Q-5_M (DPAK, 5-Leads, Body 10.22x8.89mm, Pitch 1.702mm, IPC Low Density)
pins: 1 VC, 2 FB (in), 3 GND (power), 4 VSW (power), 5 VIN (power), 6 TAB

## LT1210CR_OP_AMP
designator U?, comment LT1210CR OP AMP
Detail: RS; Costo: 11,99; ContoLavoro: 0
footprint D2PAK7_TO263_7
pins: 1 -IN (in), 2 +IN (in), 3 SHUTDOWN (power), 4 V+ (power), 5 COMP (power), 6 V- (power), 7 OUT (out), 8 V+ (power)

## LT1962
designator U?
300mA, Low Noise,  Micropower  LDO Regulators; Max Input Voltage: 20 V; Min Input Voltage: -20 V; Supply Voltage: -20 - +20 V; Aggiornato: NO; Costo: 0
footprint TSOP65P490-8AN
pins: 1 VOUT (power) "SPI Data Output. Data is output when the device is in read mode.", 2 ADJ (in) "DC Backup Power Input for Primary Cell.", 3 BYP (in) "Serial Clock Input. Used to control the timing of data in and out.", 4 GND (power) "Ground", 5 ~{SHDN} (power) "Ground", 6 NC (power) "Ground", 7 NC (power) "Ground", 8 VIN (power) "SPI Chip-Select Input. Used to select or deselect the device."

## LT3748EMS
designator U?
Aggiornato: NO; Costo: 0
footprint MSOP_16
pins: 1 VIN, 2 NC, 3 EN/UVLO, 4 NC, 5 INTVcc, 6 GATE, 7 SENSE, 8 GND, 9 GND, 10 SS, 11 Vc, 12 TC, 13 NC, 14 Rref, 15 NC, 16 Rfb

## LT3790
designator U?  (value not drawn)
LT3790 60V Synchronous 4-Switch  Buck-Boost Controller; Aggiornato: NO; Costo: 7; ContoLavoro: 0
footprint TSSOP38
footprint TSSOP38_MOD_PAD (TSSOP38 ISOLAMENTO PAD AUMENTATO)
pins: 1 CTRL, 2 SS, 3 PWM, 4 C/10, 5 SHORT, 6 Vref, 7 ISMON, 8 IVINMON, 9 EN/UVLO, 10 IVINP, 11 IVINN, 12 Vin, 13 INTVcc, 14 TG1, 15 BST1, 16 SW1, 17 PGND, 18 BG1, 19 BG2, 20 PGND, 21 SW2, 22 BST2, 23 NC, 24 TG2, 25 ISP, 26 ISN, 27 SNSP, 28 SNSN, 29 TEST1, 30 SGND, 31 PWMOUT, 32 CCM, 33 CLKOUT, 34 SYNC, 35 RT, 36 Vc, 37 FB, 38 OVLO, 39 SGND_PAD

## LT8471
designator U?  (value not drawn)
LT8471 Dual Multitopology  DC/DC Converters with 2A  Switches and Synchronization; Aggiornato: NO; Costo: 0
pins: 1 E1, 2 Vin1, 3 PG1, 4 FB1, 5 OV/UV, 6 RT, 7 SS1, 8 SYNC, 9 GND, 10 GND, 11 GND, 12 GND, 13 GND, 14 GND, 15 NC, 16 C3, 17 SHOUT, 18 SS2, 19 FB2, 20 PG2, 21 Vin2, 22 E2, 23 NC, 24 NC, 25 C2, 26 C1, 27 NC, 28 NC

## LT8580
designator U?
Detail: RS LT x 1000pz ?  FARNELL 2,91€ >100pz; Aggiornato: SI; Costo: 6,16; ContoLavoro: 1
footprint MSOP_8_EXPAD
pins: 1 FBX, 2 VC, 3 Vin, 4 SW, 5 ~{SHDN}, 6 RT, 7 SS, 8 SYNC, 9 ExposedPad

## LT8705EUHF#PBF
designator U?
Manufacturer: Linear Technology; Frequency Adjust Range: 100kHz - 400kHz; Costo: 5,57; Aggiornato: s; ContoLavoro: 1; HPcode: ICLT8705
footprint LT-UHF-38_L_MOD (QFN, 38-Leads, Body 7.1x5.1mm, Pitch 0.5mm, Thermal Pad 3.15x5.15mm, IPC High Density)
pins: 1 ~{SHDN} "Shutdown Pin. Tie high to enable device. Ground to shut down and reduce quiescent current to a minimum. Do not float this pin.", 2 CSN "The (-) Input to the Inductor Current Sense and Reverse-Current Detect Amplifier.", 3 CSP "The (+) Input to the Inductor Current Sense and Reverse-Current Detect Amplifier. The VC pin voltage and built-in offsets between CSP and CSN pins, in conjunction with the RSENSE resistor value, set the current trip (See Datasheet)", 4 LDO33 "3.3V Regulator Output. Bypass this pin to ground with a minimum 0.1uF ceramic capacitor.", 5 FBIN "Input Feedback Pin. This pin is connected to the input error amplifier input.", 6 FBO "Output Feedback Pin. This pin connects the error amplifier input to an external resistor divider from the output.", 7 IMON_OUT "Output Current Monitor Pin. The current out of this pin is proportional to the output current. See the Operation and Applications Information sections.", 8 VC "Error Amplifier Output Pin. Tie external compensation network to this pin.", 9 SS "Soft-Start Pin. Place at least 100nF of capacitance here. Upon start-up, this pin will be charged by an internal resistor to 2.5V.", 10 CLKOUT "Clock Output Pin. Use this pin to synchronize one or more compatible switching regulator ICs to the LT8705. CLKOUT toggles at the same frequency as the internal oscillator or as the SYNC pin, but is approximately 180degrees (See Datasheet)", 11 SYNC "To synchronize the switching frequency to an outside clock, simply drive this pin with a clock. The high voltage level of the clock needs to exceed 1.3V, and the low level should be less than 0.5V. Drive this pin to less (See Datasheet)", 12 RT "Timing Resistor Pin. Adjusts the switching frequency. Place a resistor from this pin to ground to set the free-running frequency. Do not float this pin.", 13 GND "Ground. Tie directly to local ground plane.", 14 BG1 "Bottom Gate Drive. Drives the gates of the bottom N-channel MOSFETs between ground and GATEVCC.", 15 GATEVCC "Power Supply for Gate Drivers. Must be connected to the INTVCC pin. Do not power from any other supply. Locally bypass to GND.", 16 BG2 "Bottom Gate Drive. Drives the gates of the bottom N-channel MOSFETs between ground and GATEVCC.", 17 BOOST2 "Boosted Floating Driver Supply. The (+) terminal of the bootstrap capacitor connects here. The BOOST1 pin swings from a diode voltage below GATEVCC up to VIN + GATEVCC. The BOOST2 pin swings from a diode voltage below (See Datasheet)", 18 TG2 "Top Gate Drive. Drives the top N-channel MOSFETs with voltage swings equal to GATEVCC superimposed on the switch node voltages.", 19 SW2 "Switch Nodes. The (-) terminals of the bootstrap capacitors connect here.", 20 NC, 21 SW1 "Switch Nodes. The (-) terminals of the bootstrap capacitors connect here.", 22 TG1 "Top Gate Drive. Drives the top N-channel MOSFETs with voltage swings equal to GATEVCC superimposed on the switch node voltages.", 23 BOOST1 "Boosted Floating Driver Supply. The (+) terminal of the bootstrap capacitor connects here. The BOOST1 pin swings from a diode voltage below GATEVCC up to VIN + GATEVCC. The BOOST2 pin swings from a diode voltage below (See Datasheet)", 24 NC, 25 SRVO_FBIN "Open-Drain Logic Output. This pin is pulled to ground when the input voltage feedback loop is active.", 26 SRVO_IIN "Open-Drain Logic Output. The pin is pulled to ground when the input current loop is active.", 27 SRVO_IOUT "Open-Drain Logic Output. The pin is pulled to ground when the output current feedback loop is active.", 28 SRVO_FBOUT "Open-Drain Logic Output. This pin is pulled to ground when the output voltage feedback loop is active.", 29 EXTVCC "External VCC Input. When EXTVCC exceeds 6.4V (typical), INTVCC will be powered from this pin. When EXTVCC is lower than 6.22V (typical), INTVCC will be powered from VIN.", 30 CSNOUT "The (-) Input to the Output Current Monitor Amplifier. Connect this pin to VOUT when not in use. See Applications Information section for proper use of this pin.", 31 CSPOUT "The (+) Input to the Output Current Monitor Amplifier. This pin and the CSNOUT pin measure the voltage across the sense resistor, RSENSE2, to provide the output current signals. Connect this pin to VOUT when not in use. See (See Datasheet)", 32 CSNIN "The (-) Input to the Input Current Monitor Amplifier. This pin and the CSPIN pin measure the voltage across the sense resistor, RSENSE1, to provide the input current signals. Connect this pin to VIN when not in use. See (See Datasheet)", 33 CSPIN "The (+) Input to the Input Current Monitor Amplifier. Connect this pin to VIN when not in use. See Applications Information section for proper use of this pin.", 34 VIN "Main Input Supply Pin. It must be locally bypassed to ground.", 35 INTVCC "Internal 6.35V Regulator Output. Must be connected to the GATEVCC pin. INTVCC is powered from EXTVCC when the EXTVCC voltage is higher than 6.4V, otherwise INTVCC is powered from VIN . Bypass this pin to ground with a (See Datasheet)", 36 SWEN "Switch Enable Pin. Tie high to enable switching. Ground to disable switching. Don’t float this pin. This pin is internally tied to INTVCC in the TSSOP package.", 37 MODE "Mode Pin. The voltage applied to this pin sets the operating mode of the controller. When the applied voltage is less than 0.4V, the forced continuous current mode is active. When this pin is allowed to float, Burst Mode (See Datasheet)", 38 IMON_IN "Input Current Monitor Pin. The current out of this pin is proportional to the input current. See the Operation and Applications Information sections.", 39 EP "Ground. Tie directly to local ground plane."

## LTC3260EDE#PBF
designator U?
LTC3260; Aggiornato: s; Costo: 3,80; ContoLavoro: 1
footprint DFN_14 (Footprint not found)
pins: 1 EN+, 2 RT, 3 BYP-, 4 ADJ-, 5 LDO-, 6 Vout, 7 C-, 8 C+, 9 Vin, 10 LDO+, 11 EN-, 12 MODE, 13 ADJ+, 14 BYP+, 15 ExposedPad

## LTC3260EMSE#PBF
designator U?
LTC3260 MSOP16; Detail: >250pz; Aggiornato: s; Costo: 4,2; ContoLavoro: 1
footprint MSOP_16_EXPAD (Footprint not found)
pins: 1 EN+, 2 RT, 3 BYP-, 4 ADJ-, 5 LDO-, 6 Vout, 7 C-, 8 NC, 9 NC, 10 C+, 11 Vin, 12 LDO+, 13 EN-, 14 MODE, 15 ADJ+, 16 BYP+, 17 ExposedPad

## LTC3261
designator U?
Detail: LT x 1000pz 3,74 RS >50pz; Aggiornato: SI; Costo: 2,87; ContoLavoro: 1
footprint MSOP_12_EXPAD (MSOP 12)
pins: 1 NC, 2 RT, 3 NC, 4 Vout, 5 C-, 6 NC, 7 NC, 8 C+, 9 Vin, 10 EN, 11 MODE, 12 NC, 13 ExposedPad

## LTC6906
designator U?
Aggiornato: NO; Costo: 0
footprint SOT-23 6PIN
pins: 1 V+, 2 GND, 3 DIV, 4 SET, 5 GRD, 6 OUT

## LTV-817S-TA1-C
designator U?, comment LTV-817S
LTV-817S-TA1-C; Aggiornato: NO; Costo: 0,05; ContoLavoro: 0
footprint LTV-817S
pins: 1, 2, 3, 4

## M25P80
designator U?, comment M25P80-VMW6 8Mbit Serial Flash
Bit Width: Bits; Supply Voltage: mV; Aggiornato: NO; Costo: 0
footprint SOIC8-200-BODY
pins: 1 ~{S} (in), 2 Q (hiz) "Serial Output", 3 ~{W} (in) "Serial Output", 4 VSS (power) "Serial Output", 5 D (in) "Serial Input", 6 C (in) "Serial Input", 7 HOL~{D} (in) "Serial Input", 8 VCC (power) "Serial Input"

## M93C56
designator U?
Aggiornato: NO; Costo: 0,285; Detail: € RS pz>50; ContoLavoro: 0
footprint SO8
footprint SOIC150-8N
pins: 1 CS, 2 SK, 3 DIN, 4 DOUT, 5 GND, 6 NC, 7 NC, 8 VCC

## MAX485CSA+
designator U?
Costo: 1,99; Aggiornato: S; ContoLavoro: 0
footprint SOIC150-8N
pins: 1 RO, 2 RE/, 3 DE, 4 DI, 5 GND, 6 A, 7 B, 8 VCC

## MAX1037
designator U?, comment MAX1037EKA-T
MAX1037EKA-T, 2.7V to 5.5V, Low-Power, 4-Channel, I2C, 8-Bit ADCs; Aggiornato: NO; Costo: 0
footprint SOT65P280-8
pins: 1 AIN0 (in) "Analog Input 0", 2 AIN1 (in) "Analog Input 0", 3 AIN2 (in) "Analog Input 0", 4 AIN3/REF (power) "Analog Input 3/ Reference Input", 5 SCL (io) "I2C Clock Line", 6 SDA (io) "I2C Data Line", 7 GND (power), 8 VDD (power) "Positive Supply"

## MAX1556
designator U?
16uA IQ, 1.2A PWM  Step-Down DC-DC Converters; Max Input Voltage: 20 V; Max Output Current: 300 mA; Min Input Voltage: -20 V; Supply Voltage: -20 - +20 V; Aggiornato: NO; Costo: 0
footprint QFN50P300X300X80-10L
pins: 1 VIN (power) "SPI Chip-Select Input. Used to select or deselect the device.", 2 GND (power) "Ground", 3 SS "Ground", 4 OUT "DC Backup Power Input for Primary Cell.", 5 ~{SHDN} (power) "Ground", 6 D2 (in) "Ground", 7 PG (power) "Serial Clock Input. Used to control the timing of data in and out.", 8 LX "SPI Data Output. Data is output when the device is in read mode.", 9 INP (power) "Ground", 10 D1 (in) "Ground", 11 EP(GND) (power) "Ground"

## MAX1806
designator U?
MAX1806, 500mA Linear Regulator; Max Input Voltage: 5.5 V; Max Output Voltage: mV; Min Input Voltage: 2.25 V; Min Output Voltage: 0.8 V; Aggiornato: NO; Costo: 0
footprint SOP65P490-8
pins: 1 IN, 2 IN, 3 POK, 4 SHDN, 5 GND, 6 SET, 7 OUT, 8 OUT

## MAX1831
designator U?, comment MAX1831EEE
MAX1831EEE, 3A, 1MHz, Low-Voltage, Step-Down Regulators with Synchronous Rectification and Internal Switches; Max Input Voltage: 5.5 V; Max Output Voltage: 5.5 mV; Min Input Voltage: 3 V; Min Output Voltage: 1.084 V; Supply Voltage: mV; Aggiornato: NO; Costo: 0
footprint SOP63P602-16
pins: 1 LX (out), 2 IN (in), 3 LX (out), 4 IN (in), 5 ~{SHDN} (in), 6 COMP (in), 7 TOFF (in), 8 FB (in), 9 AGND (power), 10 REF (in), 11 FBSEL, 12 VCC (power), 13 PGND (power), 14 LX (out), 15 PGND (power), 16 LX (out)

## MAX1831-ALT
designator U1_PS?, comment MAX1831EEE
MAX1831EEE, 3A, 1MHz, Low-Voltage, Step-Down Regulators with Synchronous Rectification and Internal Switches; Max Input Voltage: 5.5 V; Max Output Voltage: 5.5 mV; Min Input Voltage: 3 V; Min Output Voltage: 1.084 V; Supply Voltage: mV; Aggiornato: NO; Costo: 0
footprint SOP63P602-16
pins: 1 LX (power), 2 IN (power), 3 LX (power), 4 IN (power), 5 ~{SHDN} (in), 6 COMP (in), 7 TOFF (in), 8 FB (in), 9 AGND (power), 10 REF (in), 11 FBSEL, 12 VCC (power), 13 PGND (power), 14 LX (power), 15 PGND (power), 16 LX (power)

## MAX3051EKA-T
designator U?
Aggiornato: NO; Costo: 0
footprint SOT65P280-8
pins: 1 TXD (in) "Screw Terminal", 2 GND (power), 3 VDD (power) "Positive Supply 4.5V to 5.5V", 4 RXD (out) "Receive Data", 5 VREF (out) "Reference Voltage", 6 CANL (out) "CAN Bus Low Line", 7 CANH (out) "CAN Bus High Line", 8 RS "Mode/Slope Setting"

## MAX3072EESA
designator U?
Costo: 1,27; Aggiornato: S; ContoLavoro: 0
footprint SOIC150-8N
pins: 1 RO, 2 RE/, 3 DE, 4 DI, 5 GND, 6 A, 7 B, 8 VCC

## MAX3232
designator U?, comment HIN232ACBNZ-T
HIN232ACBNZ-T 5V,  True RS-232 Transceivers; Aggiornato: NO; Costo: 0
footprint SOIC127P600-16
pins: 1 C1+, 2 V+ (power), 3 C1-, 4 C2+, 5 C2-, 6 V- (power), 7 T2OUT (out), 8 R2IN (in), 9 R2OUT (out), 10 T2IN (in), 11 T1IN (in), 12 R1OUT (out), 13 R1IN (in), 14 T1OUT (out), 15 GND (power), 16 VCC (power)

## MAX3232_1
designator U?, comment MAX3232EUE
MAX3232EUE, 3.0V to 5.5V, Low-Power, up to 1Mbps, True RS-232 Transceivers Using Four 0.1µF External Capacitors; Aggiornato: NO; Costo: 0
footprint TSOP65P638-16
pins: 1 C1+, 2 V+ (power), 3 C1-, 4 C2+, 5 C2-, 6 V- (power), 7 T2OUT (out), 8 R2IN (in), 9 R2OUT (out), 10 T2IN (in), 11 T1IN (in), 12 R1OUT (out), 13 R1IN (in), 14 T1OUT (out), 15 GND (power), 16 VCC (power)

## MAX3362
designator U?
MAX3362 3.3V, High-Speed, RS-485/RS-422 Transceiver in  SOT Package; Aggiornato: NO; Costo: 0
footprint SOT23-8
pins: 1 RO (out), 2 ~{RE} (in), 3 DE (in), 4 DI (in), 5 GND (power), 6 A (io), 7 B (io), 8 VCC (power)

## MAX4372
designator U?
MAX4372 High Side Current Sense Amplifier; Max Input Voltage: mV; Max Output Current: mA; Aggiornato: NO; Costo: 0
footprint SOT-23-5
pins: 1 GND (power), 2 OUT, 3 VCC (power), 4 RS+, 5 RS-


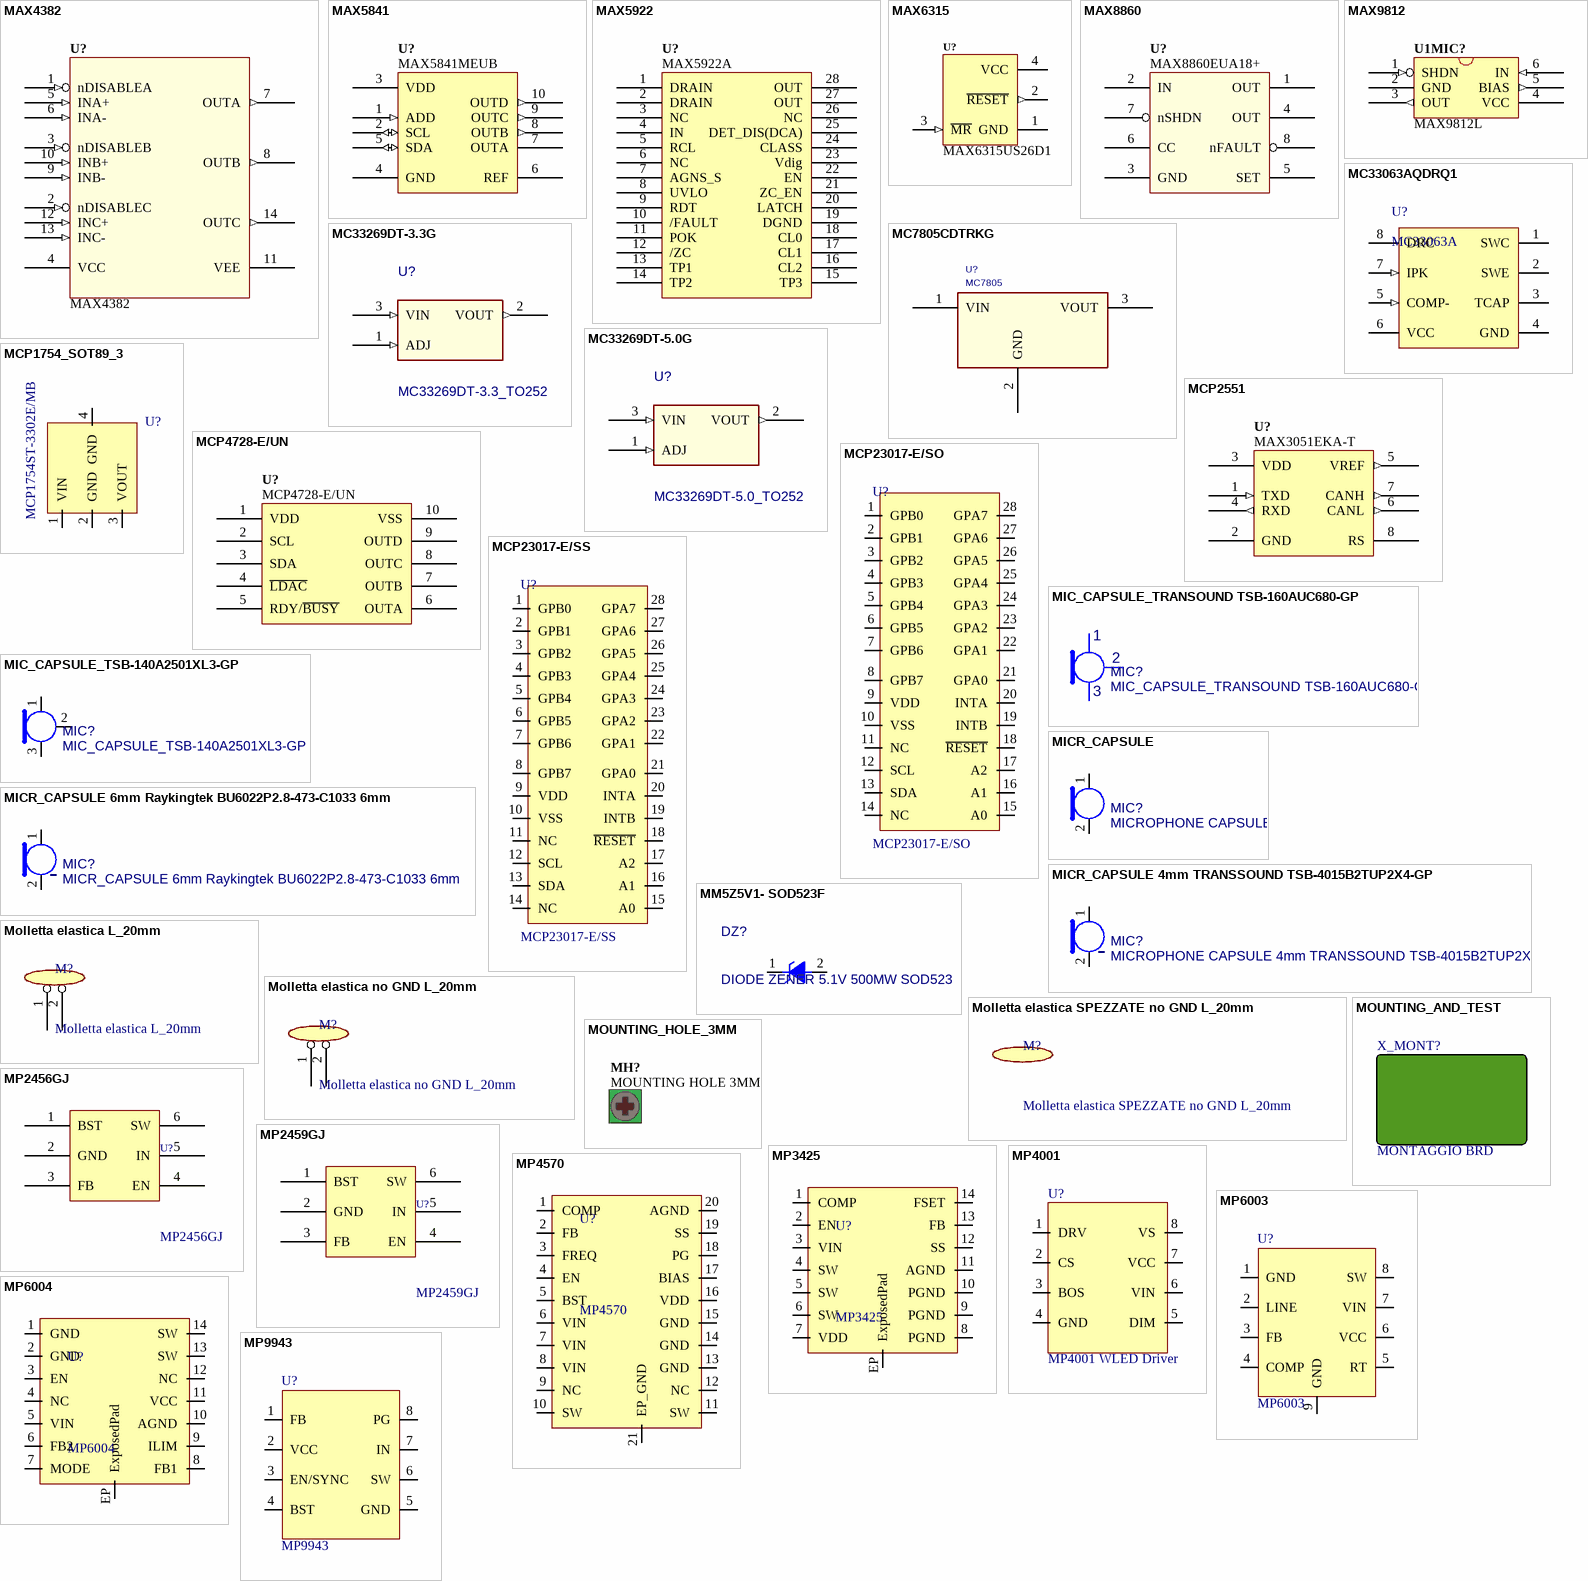
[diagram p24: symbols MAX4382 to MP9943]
## MAX4382
designator U?
MAX4382 OPAMP, TSSOP14; Aggiornato: NO; Costo: 0
footprint TSSOP-14
pins: 1 nDISABLEA (in), 2 nDISABLEC (in), 3 nDISABLEB (in), 4 VCC (power), 5 INA+ (in), 6 INA- (in), 7 OUTA (out), 8 OUTB (out), 9 INB- (in), 10 INB+ (in), 11 VEE (power), 12 INC+ (in), 13 INC- (in), 14 OUTC (out)

## MAX5841
designator U?, comment MAX5841MEUB
MAX5841MEUB, Quad, 10-Bit, Low-Power, I2C, DAC; Aggiornato: NO; Costo: 0
footprint TSSOP50P490-10
pins: 1 ADD (in) "I2C Address Select", 2 SCL (io) "I2C Clock", 3 VDD (power) "Positive Supply 2.7V to 5.5V", 4 GND (power), 5 SDA (io) "GND", 6 REF "Reference Voltage Input 1V to VDD", 7 OUTA "DAC Output", 8 OUTB (out) "DAC Output", 9 OUTC (out) "DAC Output", 10 OUTD (out) "DAC Output"

## MAX5922
designator U?, comment MAX5922A
MAX5922A, PoE Controller; Max Input Voltage: mV; Max Output Current: mA; Aggiornato: NO; Costo: 0
footprint TSOP65P640-28
pins: 1 DRAIN, 2 DRAIN, 3 NC, 4 IN, 5 RCL, 6 NC, 7 AGNS_S, 8 UVLO, 9 RDT, 10 /FAULT, 11 POK, 12 /ZC, 13 TP1, 14 TP2, 15 TP3, 16 CL2, 17 CL1, 18 CL0, 19 DGND, 20 LATCH, 21 ZC_EN, 22 EN, 23 Vdig, 24 CLASS, 25 DET_DIS(DCA), 26 NC, 27 OUT, 28 OUT

## MAX6315
designator U?, comment MAX6315US26D1
MAX6315, Open-Drain Output SOT Reset IC, Customized Reset Thresholds, Timeout Delays; Aggiornato: NO; Costo: 0
footprint SOT143
pins: 1 GND (power), 2 ~{RESET} (out), 3 ~{MR} (in), 4 VCC (power)

## MAX8860
designator U?, comment MAX8860EUA18+
MAX8860EUA18+, 1.8V Linear Regulator with adjustable Output, Low-noise, Low-dropout, 300mA, uMAX; Max Input Voltage: 6.5 V; Max Output Voltage: 5.5 V; Min Input Voltage: 2.5 V; Min Output Voltage: 1.25 V; Supply Voltage: 2.5 to 6.5 V; Aggiornato: NO; Costo: 0
footprint SOP65P490-8
pins: 1 OUT, 2 IN, 3 GND, 4 OUT, 5 SET, 6 CC, 7 nSHDN, 8 nFAULT

## MAX9812
designator U1MIC?, comment MAX9812L
MAX9812L, Microphone Pre-Amplifier, single, 20dB gain, Shutdown; Supply Voltage: 2.7-3.6 mV; Aggiornato: NO; Costo: 0
footprint SC70_6L
pins: 1 SHDN (in), 2 GND (power), 3 OUT (out), 4 VCC (power), 5 BIAS (out), 6 IN (in)

## MC7805CDTRKG
designator U?, comment MC7805
MC7805CDTRKG Voltage Regulator 7805; Costo: 0,30; Aggiornato: s; ContoLavoro: 0
footprint SM/_DPAK
pins: 1 VIN, 2 GND, 3 VOUT

## MC33063AQDRQ1
designator U?, comment MC33063A
Inverting Buck-Boost Regulator with 3 to 40 V Input and 1.25 to 40 V Output, -40 to 125 degC, 8-Pin SOIC (D), Green (RoHS & no Sb/Br); Manufacturer: Texas Instruments; PartNumber: MC33063AQDRQ1; Regulated Outputs(#): 1; SubFamily: Inverting Regulator; Switch Current Limit(Typ)(A): 1.5; Switching Frequency(Max)(kHz): 100; Vin(Max)(V): 40; Vin(Min)(V): 3; Vout(Min)(V): 1.25; Costo: 0; Aggiornato: no+
footprint SOIC150-8N
pins: 1 SWC (oc), 2 SWE (oe), 3 TCAP, 4 GND (power), 5 COMP- (in), 6 VCC (power), 7 IPK (in), 8 DRC (oc)

## MC33269DT-3.3G
designator U?, comment MC33269DT-3.3_TO252
Costo: 0,536; DeviceFunction: Voltage Regulator; Aggiornato: SI; ContoLavoro: 0
footprint DPACK_TO252
pins: 1 ADJ (in), 2 VOUT (out), 3 VIN (in)

## MC33269DT-5.0G
designator U?, comment MC33269DT-5.0_TO252
Costo: 0; DeviceFunction: Voltage Regulator; Aggiornato: SI
footprint DPACK_TO252
pins: 1 ADJ (in), 2 VOUT (out), 3 VIN (in)

## MCP1754_SOT89_3
designator U?, comment MCP1754ST-3302E/MB
Costo: 0,6; Aggiornato: NO; ContoLavoro: 0
footprint SOT89-3
pins: 1 VIN, 2 GND, 3 VOUT, 4 GND

## MCP2551
designator U?, comment MAX3051EKA-T
Aggiornato: NO; Costo: 0
footprint SOT65P280-8
pins: 1 TXD (in) "Screw Terminal", 2 GND (power), 3 VDD (power) "Positive Supply 4.5V to 5.5V", 4 RXD (out) "Receive Data", 5 VREF (out) "Reference Voltage", 6 CANL (out) "CAN Bus Low Line", 7 CANH (out) "CAN Bus High Line", 8 RS "Mode/Slope Setting"

## MCP4728-E/UN
designator U?
MCP4728-E/UN, 12-Bit, Quad Digital-to-Analog Converter with EEPROM Memory; Aggiornato: NO; Costo: 0
footprint MSOP_10 (MSOP 10)
pins: 1 VDD "Positive Supply 2.7V to 5.5V", 2 SCL "I2C Clock", 3 SDA "I2C Data", 4 ~{LDAC} (power) "Latch data", 5 RDY/~{BUSY}, 6 OUTA "DAC Output", 7 OUTB "DAC Output", 8 OUTC "DAC Output", 9 OUTD "DAC Output", 10 VSS "GND"

## MCP23017-E/SO
designator U?
Costo: 1,068; Aggiornato: S; ContoLavoro: 0
footprint SOIC28-WIDE
pins: 1 GPB0, 2 GPB1, 3 GPB2, 4 GPB3, 5 GPB4, 6 GPB5, 7 GPB6, 8 GPB7, 9 VDD, 10 VSS, 11 NC, 12 SCL, 13 SDA, 14 NC, 15 A0, 16 A1, 17 A2, 18 ~{RESET}, 19 INTB, 20 INTA, 21 GPA0, 22 GPA1, 23 GPA2, 24 GPA3, 25 GPA4, 26 GPA5, 27 GPA6, 28 GPA7

## MCP23017-E/SS
designator U?
Costo: 1,09; Aggiornato: S; ContoLavoro: 0
footprint SSOP_28
pins: 1 GPB0, 2 GPB1, 3 GPB2, 4 GPB3, 5 GPB4, 6 GPB5, 7 GPB6, 8 GPB7, 9 VDD, 10 VSS, 11 NC, 12 SCL, 13 SDA, 14 NC, 15 A0, 16 A1, 17 A2, 18 ~{RESET}, 19 INTB, 20 INTA, 21 GPA0, 22 GPA1, 23 GPA2, 24 GPA3, 25 GPA4, 26 GPA5, 27 GPA6, 28 GPA7

## MIC_CAPSULE_TRANSOUND TSB-160AUC680-GP
designator MIC?  (mechanical)
Costo: 0; Aggiornato: S; ContoLavoro: 1

## MIC_CAPSULE_TSB-140A2501XL3-GP
designator MIC?
MICROPHONE CAPSULE TSB-140A2501XL3-GP; Hpcode: MMMIC001; Costo: 1,7; Aggiornato: S; ContoLavoro: 1
footprint MICROPHONE TSB-140A2501XL3-GP_ALLARGATA_BORDOSCHEDA
footprint MICROPHONE TSB-140A2501XL3-GP_ALLARGATA
pins: 1, 2, 3

## MICR_CAPSULE
designator MIC?, comment MICROPHONE CAPSULE
Costo: 0; Aggiornato: S
footprint MICROPHONE_SIDE_ONE_LAYER
pins: 1, 2

## MICR_CAPSULE 4mm TRANSSOUND TSB-4015B2TUP2X4-GP
designator MIC?, comment MICROPHONE CAPSULE 4mm TRANSSOUND TSB-4015B2TUP2X4-GP
Hpcode: MIC04X1MM536DBEL; Detail: TRANSSOUND prezzo per >12Kpz; Costo: 0,85; Aggiornato: S; ContoLavoro: 1
footprint MICROPHONE_SIDE_ONE_LAYER
pins: 1, 2

## MICR_CAPSULE 6mm Raykingtek BU6022P2.8-473-C1033 6mm
designator MIC?
Hpcode: MIC06X2MM3; Aggiornato: S; ContoLavoro: 1
footprint MICROPHONE Raykingtek BU6022P2.8-473-C1033 6mm
pins: 1, 2

## MM5Z5V1- SOD523F
designator DZ?, comment DIODE ZENER 5.1V 500MW SOD523
Zener Diode 5.1 V 500 mW ±2% Surface Mount SOD-523; Detail: 67,92€ per 100pz digikey; Aggiornato: SI; Costo: 0,06792; ContoLavoro: 0
footprint SOD523 - MM5Z5V1
pins: 1, 2

## Molletta elastica L_20mm
designator M?  (no BOM)
Aggiornato: NO; Costo: 0
footprint Molletta elastica L_20mm
pins: 1, 2

## Molletta elastica no GND L_20mm
designator M?  (no BOM)
Costo: 0
footprint Molletta elastica no GND L_20mm
pins: 1, 2

## Molletta elastica SPEZZATE no GND L_20mm
designator M?  (no BOM)
Costo: 0
footprint Molletta elastica SPEZZATE no GND L_20mm

## MOUNTING_AND_TEST
designator X_MONT?, comment MONTAGGIO BRD  (mechanical)
Montaggio e collaudo; Costo: 0

## MOUNTING_HOLE_3MM
designator MH?, comment MOUNTING HOLE 3MM  (no BOM)
Mounting Hole, M3 Screw, Plated, Square Pad; Aggiornato: NO; Costo: 0
footprint MOUNTING_HOLE_3MM
pins: 1 hidden

## MP2456GJ
designator U?
Costo: 0,69; Hpcode: ICMP2456GJ-P; Aggiornato: SI; Detail: prezzo Melchioni per 500pz; ContoLavoro: 1
footprint TSOT-23-6
pins: 1 BST, 2 GND, 3 FB, 4 EN, 5 IN, 6 SW

## MP2459GJ
designator U?
Costo: 0; Hpcode: da fare qualcosa tipo ICMP2459GJ; Aggiornato: n; Detail: chiedere prezzo Melchioni; ContoLavoro: 1
footprint TSOT-23-6
pins: 1 BST, 2 GND, 3 FB, 4 EN, 5 IN, 6 SW

## MP3425
designator U?
Detail: €2,32 con cambio 1€=1,10usd; Hpcode: ICMP3425DL-LF-P; Costo: 2,32; Aggiornato: S; ContoLavoro: 1
footprint QFN-14_MP3425 (Footprint not found)
pins: 1 COMP, 2 EN, 3 VIN, 4 SW, 5 SW, 6 SW, 7 VDD, 8 PGND, 9 PGND, 10 PGND, 11 AGND, 12 SS, 13 FB, 14 FSET, EP ExposedPad

## MP4001
designator U?, comment MP4001 WLED Driver
Costo: 0; Aggiornato: NO
footprint SO8
pins: 1 DRV, 2 CS, 3 BOS, 4 GND, 5 DIM, 6 VIN, 7 VCC, 8 VS

## MP4570
designator U?
Step-Down converter; Detail: 1,10 USD; Hpcode: ICMP4570; Costo: 1,05; Aggiornato: s; ContoLavoro: 1
footprint TSSOP20EP-MP4570 (TSSOP20 Exposed Pad)
pins: 1 COMP, 2 FB, 3 FREQ, 4 EN, 5 BST, 6 VIN, 7 VIN, 8 VIN, 9 NC, 10 SW, 11 SW, 12 NC, 13 GND, 14 GND, 15 GND, 16 VDD, 17 BIAS, 18 PG, 19 SS, 20 AGND, 21 EP_GND

## MP6003
designator U?
MP6003 Monolithic Flyback/SEPIC DC-DC Converter; Costo: 1,72; Detail: 1,72€ x 25pz; Aggiornato: SI; ContoLavoro: 0
footprint SOIC8E
pins: 1 GND, 2 LINE, 3 FB, 4 COMP, 5 RT, 6 VCC, 7 VIN, 8 SW "Vout", 9 GND "Exposed PAD"

## MP6004
designator U?
Costo: 0; Aggiornato: n
footprint QFN-14_MP6004 (Footprint not found)
pins: 1 GND, 2 GND, 3 EN, 4 NC, 5 VIN, 6 FB2, 7 MODE, 8 FB1, 9 ILIM, 10 AGND, 11 VCC, 12 NC, 13 SW, 14 SW, EP ExposedPad

## MP9943
designator U?
MP9943 3A Peak Synchronous Step Down Converter; Costo: 2,00; Detail: 2,00€ x 25pz; Aggiornato: SI; ContoLavoro: 0
footprint QFN8_MPS (QFN8_Monolithic_3x3_)
pins: 1 FB, 2 VCC, 3 EN/SYNC, 4 BST, 5 GND, 6 SW "Output", 7 IN, 8 PG "Power Good"


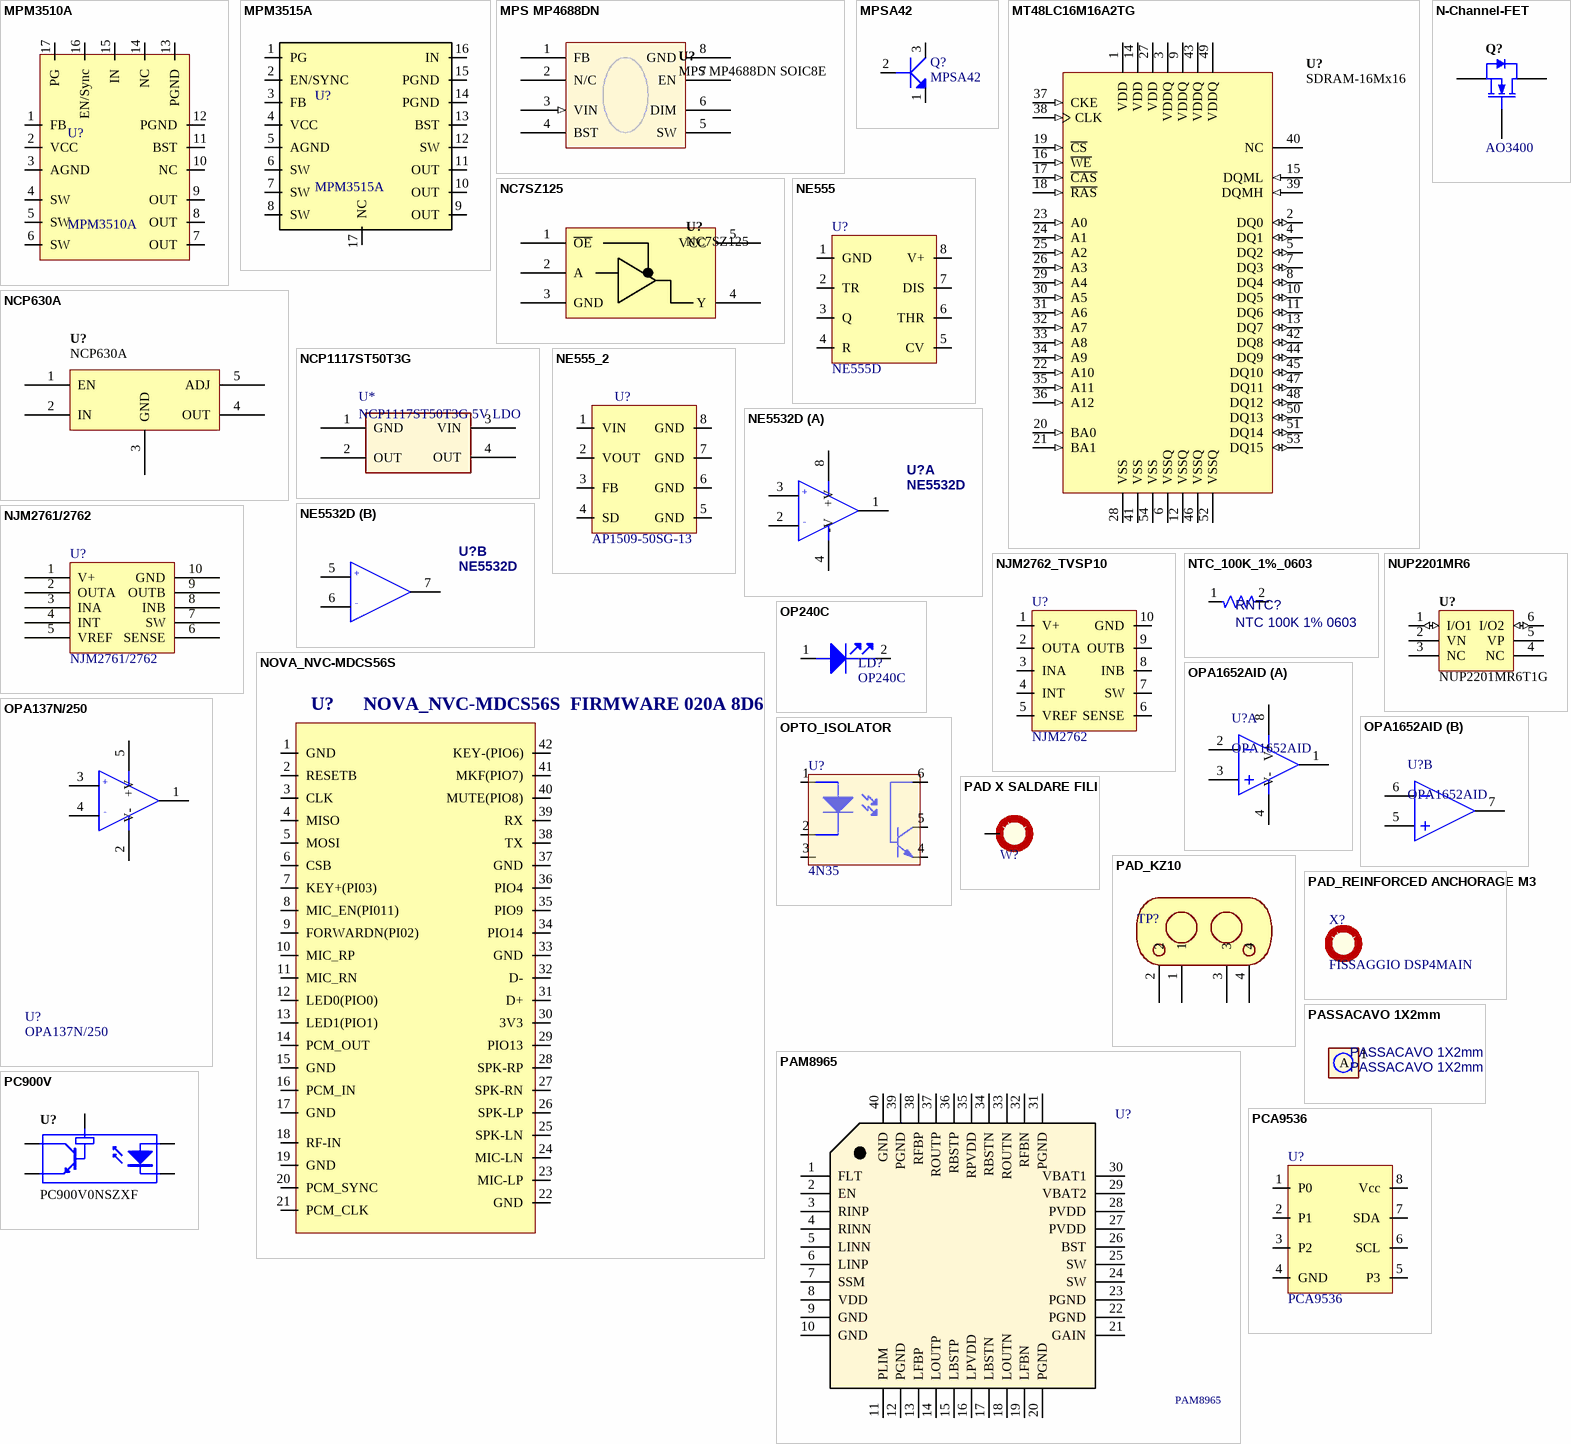
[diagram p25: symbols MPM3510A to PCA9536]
## MPM3510A
designator U?
Step-Down converter with integrated inductor; Hpcode: ICMPM3510A; Costo: 1,2; Aggiornato: s; ContoLavoro: 1
footprint QFN-19_MPM3510A (Footprint not found)
pins: 1 FB, 2 VCC, 3 AGND, 4 SW, 5 SW, 6 SW, 7 OUT, 8 OUT, 9 OUT, 10 NC, 11 BST, 12 PGND, 13 PGND, 14 NC, 15 IN, 16 EN/Sync, 17 PG, 19 NC hidden, 20 NC hidden

## MPM3515A
designator U?
Step-Down converter with integrated inductor; Hpcode: ICMPM3515; Costo: 4; Aggiornato: s; ContoLavoro: 1
footprint QFN-17_MPM3515A
pins: 1 PG, 2 EN/SYNC, 3 FB, 4 VCC (power), 5 AGND, 6 SW, 7 SW, 8 SW, 9 OUT, 10 OUT, 11 OUT, 12 SW, 13 BST, 14 PGND, 15 PGND, 16 IN (power), 17 NC, 19 NC hidden, 20 NC hidden

## MPS MP4688DN
designator U?, comment MPS MP4688DN SOIC8E
MPS MP4688DN 55V, 1A High Power LED Driver; Aggiornato: NO; Costo: 0,89; HPcode: ICMP4688DN; ContoLavoro: 1
footprint SOIC150-8N
pins: 1 FB, 2 N/C, 3 VIN (in), 4 BST, 5 SW, 6 DIM, 7 EN, 8 GND

## MPSA42
designator Q?
Costo: 0,083; Aggiornato: s; ContoLavoro: 0
footprint TO92/100/123
pins: 1 E, 2 B, 3 C

## MT48LC16M16A2TG
designator U?, comment SDRAM-16Mx16
MT48LC16M16A2TG, 256 Mbit High-Speed CMOS SDRAM, 16Mb x 16Bit x 4 Banks, TSOP54; Bit Width: Bits; Supply Voltage: mV; Aggiornato: NO; Costo: 0
footprint TSOP80P1176-54
pins: 1 VDD (power) "Power Supply", 2 DQ0 (io) "Data Input/Output 0", 3 VDDQ (power) "DQ Power", 4 DQ1 (io) "Data Input/Output 1", 5 DQ2 (io) "Data Input/Output 2", 6 VSSQ (power) "DQ Ground", 7 DQ3 (io) "Data Input/Output 3", 8 DQ4 (io) "Data Input/Output 4", 9 VDDQ (power) "DQ Power", 10 DQ5 (io) "Data Input/Output 5", 11 DQ6 (io) "Data Input/Output 6", 12 VSSQ (power) "DQ Ground", 13 DQ7 (io) "Data Input/Output 7", 14 VDD (power) "Power Supply", 15 DQML (in) "Input/Output Mask for DQ0-DQ7", 16 ~{WE} (in) "Command Input", 17 ~{CAS} (in) "Command Input", 18 ~{RAS} (in) "Command Input", 19 ~{CS} (in) "Chip Select", 20 BA0 (in) "Bank Address Input 0", 21 BA1 (in) "Bank Address Input 1", 22 A10 (in) "Address Input 10", 23 A0 (in) "Address Input 0", 24 A1 (in) "Address Input 1", 25 A2 (in) "Address Input 2", 26 A3 (in) "Address Input 3", 27 VDD (power) "Power Supply", 28 VSS (power) "Ground", 29 A4 (in) "Address Input 4", 30 A5 (in) "Address Input 5", 31 A6 (in) "Address Input 6", 32 A7 (in) "Address Input 7", 33 A8 (in) "Address Input 8", 34 A9 (in) "Address Input 9", 35 A11 (in) "Address Input 11", 36 A12 (in) "Address Input 12", 37 CKE (in) "Clock Enable", 38 CLK (in) "Clock", 39 DQMH (in) "Input/Output Mask for DQ8-DQ15", 40 NC "No Connect", 41 VSS (power) "Ground", 42 DQ8 (io) "Data Input/Output 8", 43 VDDQ (power) "DQ Power", 44 DQ9 (io) "Data Input/Output 9", 45 DQ10 (io) "Data Input/Output 10", 46 VSSQ (power) "DQ Ground", 47 DQ11 (io) "Data Input/Output 11", 48 DQ12 (io) "Data Input/Output 12", 49 VDDQ (power) "DQ Power", 50 DQ13 (io) "Data Input/Output 13", 51 DQ14 (io) "Data Input/Output 14", 52 VSSQ (power) "DQ Ground", 53 DQ15 (io) "Data Input/Output 15", 54 VSS (power) "Ground"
